VERSION 5.7 ;
  NOWIREEXTENSIONATPIN ON ;
  DIVIDERCHAR "/" ;
  BUSBITCHARS "[]" ;
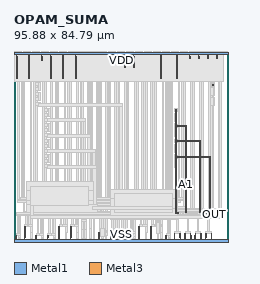
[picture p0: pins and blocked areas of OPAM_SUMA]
MACRO OPAM_SUMA
  CLASS BLOCK ;
  FOREIGN OPAM_SUMA ;
  ORIGIN 1.260 0.000 ;
  SIZE 95.880 BY 84.790 ;
  PIN VSS
    DIRECTION INOUT ;
    USE GROUND ;
    PORT
      LAYER Metal1 ;
        RECT 3.300 4.380 3.660 6.880 ;
        RECT 18.780 4.380 19.140 6.880 ;
        RECT 23.940 4.380 24.300 6.880 ;
        RECT 54.500 4.380 54.860 6.880 ;
        RECT 59.720 4.380 60.080 6.880 ;
        RECT -0.360 2.380 0.000 2.880 ;
        RECT -0.390 1.880 0.000 2.380 ;
        RECT 3.270 1.880 3.660 4.380 ;
        RECT 8.460 2.380 8.820 2.880 ;
        RECT 13.620 2.380 13.980 2.880 ;
        RECT 8.430 1.880 8.820 2.380 ;
        RECT 13.590 1.880 13.980 2.380 ;
        RECT 18.750 1.880 19.140 4.380 ;
        RECT 23.910 1.880 24.300 4.380 ;
        RECT 36.480 3.130 36.840 4.380 ;
        RECT 41.860 3.130 42.220 4.380 ;
        RECT 36.450 1.880 36.840 3.130 ;
        RECT 41.830 1.880 42.220 3.130 ;
        RECT 54.470 1.880 54.860 4.380 ;
        RECT 59.690 1.880 60.080 4.380 ;
        RECT 70.200 2.880 70.560 3.880 ;
        RECT 66.540 2.380 66.900 2.880 ;
        RECT 66.510 1.880 66.900 2.380 ;
        RECT 70.170 1.880 70.560 2.880 ;
        RECT 72.700 2.880 73.060 3.880 ;
        RECT 74.860 2.880 75.220 3.880 ;
        RECT 72.700 1.880 73.090 2.880 ;
        RECT -0.390 0.900 -0.160 1.880 ;
        RECT 3.270 0.900 3.500 1.880 ;
        RECT 8.430 0.900 8.660 1.880 ;
        RECT 13.590 0.900 13.820 1.880 ;
        RECT 18.750 0.900 18.980 1.880 ;
        RECT 23.910 0.900 24.140 1.880 ;
        RECT 36.450 0.900 36.680 1.880 ;
        RECT 41.830 0.900 42.060 1.880 ;
        RECT 54.470 0.900 54.700 1.880 ;
        RECT 59.690 0.900 59.920 1.880 ;
        RECT 66.510 0.900 66.740 1.880 ;
        RECT 70.170 0.900 70.400 1.880 ;
        RECT 72.860 0.900 73.090 1.880 ;
        RECT 74.830 1.880 75.220 2.880 ;
        RECT 77.360 2.880 77.720 3.880 ;
        RECT 79.520 2.880 79.880 3.880 ;
        RECT 77.360 1.880 77.750 2.880 ;
        RECT 74.830 0.900 75.060 1.880 ;
        RECT 77.520 0.900 77.750 1.880 ;
        RECT 79.490 1.880 79.880 2.880 ;
        RECT 82.020 2.880 82.380 3.880 ;
        RECT 84.180 2.880 84.540 3.880 ;
        RECT 82.020 1.880 82.410 2.880 ;
        RECT 79.490 0.900 79.720 1.880 ;
        RECT 82.180 0.900 82.410 1.880 ;
        RECT 84.150 1.880 84.540 2.880 ;
        RECT 86.680 2.880 87.040 3.880 ;
        RECT 86.680 1.880 87.070 2.880 ;
        RECT 84.150 0.900 84.380 1.880 ;
        RECT 86.840 0.900 87.070 1.880 ;
        RECT -1.000 0.000 94.620 0.900 ;
      LAYER Metal3 ;
        RECT -1.260 0.000 94.620 0.900 ;
    END
  END VSS
  PIN VDD
    DIRECTION INOUT ;
    USE POWER ;
    PORT
      LAYER Metal1 ;
        RECT -1.000 83.890 94.620 84.790 ;
        RECT -0.190 82.910 0.040 83.890 ;
        RECT 4.050 83.790 4.530 83.890 ;
        RECT 5.370 82.910 5.600 83.890 ;
        RECT 10.930 82.910 11.160 83.890 ;
        RECT 13.670 83.790 14.150 83.890 ;
        RECT 14.990 82.910 15.220 83.890 ;
        RECT 20.550 82.910 20.780 83.890 ;
        RECT 24.790 83.790 25.270 83.890 ;
        RECT 26.110 82.910 26.340 83.890 ;
        RECT 34.410 83.790 34.890 83.890 ;
        RECT 42.530 83.790 43.010 83.890 ;
        RECT 47.910 82.910 48.140 83.890 ;
        RECT 50.650 83.790 51.130 83.890 ;
        RECT 51.970 82.910 52.200 83.890 ;
        RECT 58.770 83.790 59.250 83.890 ;
        RECT 64.210 82.910 64.440 83.890 ;
        RECT 70.110 83.790 70.590 83.890 ;
        RECT 71.430 82.910 71.660 83.890 ;
        RECT 76.990 82.910 77.220 83.890 ;
        RECT 79.730 83.790 80.210 83.890 ;
        RECT 81.050 82.910 81.280 83.890 ;
        RECT 85.110 82.910 85.340 83.890 ;
        RECT 87.850 83.790 88.330 83.890 ;
        RECT 89.170 82.910 89.400 83.890 ;
        RECT -0.190 77.910 0.200 82.910 ;
        RECT 5.370 77.910 5.760 82.910 ;
        RECT 10.930 81.910 11.320 82.910 ;
        RECT 10.960 80.910 11.320 81.910 ;
        RECT 14.990 77.910 15.380 82.910 ;
        RECT 20.550 77.910 20.940 82.910 ;
        RECT 26.110 77.910 26.500 82.910 ;
        RECT 47.910 80.410 48.300 82.910 ;
        RECT 51.970 80.410 52.360 82.910 ;
        RECT 47.940 77.910 48.300 80.410 ;
        RECT 52.000 77.910 52.360 80.410 ;
        RECT 64.210 77.910 64.600 82.910 ;
        RECT 71.430 77.910 71.820 82.910 ;
        RECT 76.990 82.410 77.380 82.910 ;
        RECT 81.050 82.410 81.440 82.910 ;
        RECT 85.110 82.410 85.500 82.910 ;
        RECT 89.170 82.410 89.560 82.910 ;
        RECT 77.020 81.910 77.380 82.410 ;
        RECT 81.080 81.910 81.440 82.410 ;
        RECT 85.140 81.910 85.500 82.410 ;
        RECT 89.200 81.910 89.560 82.410 ;
        RECT -0.160 72.910 0.200 77.910 ;
        RECT 5.400 72.910 5.760 77.910 ;
        RECT 15.020 72.910 15.380 77.910 ;
        RECT 20.580 72.910 20.940 77.910 ;
        RECT 26.140 72.910 26.500 77.910 ;
        RECT 64.240 72.910 64.600 77.910 ;
        RECT 71.460 72.910 71.820 77.910 ;
      LAYER Metal3 ;
        RECT -1.260 83.890 94.620 84.790 ;
    END
  END VDD
  PIN OUT
    DIRECTION OUTPUT ;
    ANTENNAGATEAREA 4.000000 ;
    ANTENNADIFFAREA 9.240000 ;
    PORT
      LAYER Metal3 ;
      RECT 87.490 69.980 87.890 70.380 ;
      RECT 90.015 12.220 90.415 12.620 ;
    END
  END OUT
  PIN A1
    DIRECTION INPUT ;
    ANTENNAGATEAREA 33.049999 ;
    ANTENNADIFFAREA 1.892000 ;
    PORT
      LAYER Metal3 ;
      RECT 70.700 58.580 71.100 58.980 ;
      RECT 70.780 52.080 71.080 58.580 ;
        RECT 70.700 52.030 71.100 52.080 ;
      RECT 70.700 51.730 75.700 52.030 ;
        RECT 70.700 51.680 71.100 51.730 ;
      RECT 70.780 45.180 71.080 51.680 ;
        RECT 70.700 45.130 71.100 45.180 ;
      RECT 75.400 45.130 75.700 51.730 ;
      RECT 70.700 44.830 81.800 45.130 ;
        RECT 70.700 44.780 71.100 44.830 ;
      RECT 70.780 38.280 71.080 44.780 ;
        RECT 70.700 38.230 71.100 38.280 ;
      RECT 75.400 38.230 75.700 44.830 ;
      RECT 81.500 38.230 81.800 44.830 ;
      RECT 70.700 37.930 86.460 38.230 ;
        RECT 70.700 37.880 71.100 37.930 ;
      RECT 70.780 13.280 71.080 37.880 ;
      RECT 70.730 12.880 71.130 13.280 ;
      RECT 71.730 12.880 72.130 13.360 ;
      RECT 75.400 13.280 75.700 37.930 ;
      RECT 81.500 13.280 81.800 37.930 ;
      RECT 83.150 12.880 84.450 13.360 ;
      RECT 86.160 13.280 86.460 37.930 ;
      RECT 86.110 12.880 86.510 13.280 ;
    END
  END A1
  OBS
      LAYER Via1 ;
        RECT 70.470 40.050 71.330 43.660 ;
        RECT 13.990 42.300 14.850 45.910 ;
        RECT 0.910 1.650 1.730 2.150 ;
        RECT 11.230 1.650 12.050 2.150 ;
        RECT 16.390 1.650 17.210 2.150 ;
        RECT 67.810 1.650 68.630 2.150 ;
        RECT 37.830 1.650 38.650 2.450 ;
        RECT 43.210 1.650 44.030 2.450 ;
        RECT 46.950 1.650 47.770 2.650 ;
        RECT 48.450 1.650 49.270 2.650 ;
        RECT 50.610 1.650 51.430 2.650 ;
        RECT 52.110 1.650 52.930 2.650 ;
        RECT 0.910 2.150 1.760 2.870 ;
        RECT 11.230 2.150 12.080 2.870 ;
        RECT 16.390 2.150 17.240 2.870 ;
        RECT 67.810 2.150 68.660 2.870 ;
        RECT 0.000 2.870 1.760 2.880 ;
        RECT 8.820 2.870 10.120 2.880 ;
        RECT 13.980 2.870 15.280 2.880 ;
        RECT 66.900 2.870 68.660 2.880 ;
        RECT 39.410 1.650 40.230 2.900 ;
        RECT 44.790 1.650 45.610 2.900 ;
        RECT -0.160 2.880 1.760 3.690 ;
        RECT 8.660 2.880 10.120 3.690 ;
        RECT 10.160 2.870 12.080 3.690 ;
        RECT 13.820 2.880 15.280 3.690 ;
        RECT 15.320 2.870 17.240 3.690 ;
        RECT 66.740 2.880 68.660 3.690 ;
        RECT 62.570 1.650 63.390 3.700 ;
        RECT 46.920 2.650 47.770 3.870 ;
        RECT 48.450 2.650 49.400 3.870 ;
        RECT 50.580 2.650 51.430 3.870 ;
        RECT 52.110 2.650 52.960 3.870 ;
        RECT 70.560 3.870 72.700 3.880 ;
        RECT 75.220 3.870 77.360 3.880 ;
        RECT 79.880 3.870 82.020 3.880 ;
        RECT 84.540 3.870 86.680 3.880 ;
        RECT 6.070 1.650 6.890 4.150 ;
        RECT 21.550 1.650 22.370 4.150 ;
        RECT 26.710 1.650 27.530 4.150 ;
        RECT 57.270 1.650 58.090 4.150 ;
        RECT 64.150 1.650 64.970 4.150 ;
        RECT 37.560 2.450 38.920 4.370 ;
        RECT 39.410 2.900 40.260 4.370 ;
        RECT 42.940 2.450 44.300 4.370 ;
        RECT 44.790 2.900 45.640 4.370 ;
        RECT 36.840 4.370 40.260 4.380 ;
        RECT 42.220 4.370 45.640 4.380 ;
        RECT 70.400 3.880 72.860 4.690 ;
        RECT 75.060 3.880 77.520 4.690 ;
        RECT 79.720 3.880 82.180 4.690 ;
        RECT 84.380 3.880 86.840 4.690 ;
        RECT 46.920 3.870 49.400 4.690 ;
        RECT 50.580 3.870 52.960 4.690 ;
        RECT 36.680 4.380 40.260 5.190 ;
        RECT 42.060 4.380 45.640 5.190 ;
        RECT 28.870 1.650 29.690 5.400 ;
        RECT 30.370 1.650 31.190 5.400 ;
        RECT 32.530 1.650 33.350 5.900 ;
        RECT 34.030 1.650 34.850 5.900 ;
        RECT 37.065 5.190 39.415 6.040 ;
        RECT 42.445 5.190 44.795 6.040 ;
        RECT 6.070 4.150 6.920 6.870 ;
        RECT 21.550 4.150 22.400 6.870 ;
        RECT 26.710 4.150 27.560 6.870 ;
        RECT 57.270 4.150 58.120 6.870 ;
        RECT 62.300 3.700 63.660 6.870 ;
        RECT 64.150 4.150 65.000 6.870 ;
        RECT 3.660 6.870 4.960 6.880 ;
        RECT 19.140 6.870 20.440 6.880 ;
        RECT 24.300 6.870 25.600 6.880 ;
        RECT 54.860 6.870 56.160 6.880 ;
        RECT 60.080 6.870 61.380 6.880 ;
        RECT 3.500 6.880 4.960 7.690 ;
        RECT 5.000 6.870 6.920 7.690 ;
        RECT 18.980 6.880 20.440 7.690 ;
        RECT 20.480 6.870 22.400 7.690 ;
        RECT 24.140 6.880 25.600 7.690 ;
        RECT 25.640 6.870 27.560 7.690 ;
        RECT 54.700 6.880 56.160 7.690 ;
        RECT 56.200 6.870 58.120 7.690 ;
        RECT 59.920 6.880 61.380 7.690 ;
        RECT 61.420 6.870 65.000 7.690 ;
        RECT 61.805 7.690 64.155 8.540 ;
        RECT 28.840 5.400 29.690 9.370 ;
        RECT 30.370 5.400 31.220 9.370 ;
        RECT 28.840 9.370 31.220 10.190 ;
        RECT 32.500 5.900 33.350 10.370 ;
        RECT 34.030 5.900 34.880 10.370 ;
        RECT 32.500 10.370 34.880 11.190 ;
        RECT 67.970 3.690 68.660 11.730 ;
        RECT 80.605 4.690 81.295 11.730 ;
        RECT 0.225 3.690 0.915 11.740 ;
        RECT 1.070 3.690 1.760 11.740 ;
        RECT 5.385 7.690 6.075 11.740 ;
        RECT 6.230 7.690 6.920 11.740 ;
        RECT 20.865 7.690 21.555 11.740 ;
        RECT 21.710 7.690 22.400 11.740 ;
        RECT 26.025 7.690 26.715 11.740 ;
        RECT 26.870 7.690 27.560 11.740 ;
        RECT 37.895 6.040 38.585 11.740 ;
        RECT 38.725 6.040 39.415 11.740 ;
        RECT 39.570 5.190 40.260 11.740 ;
        RECT 43.275 6.040 43.965 11.740 ;
        RECT 44.105 6.040 44.795 11.740 ;
        RECT 44.950 5.190 45.640 11.740 ;
        RECT 56.585 7.690 57.275 11.740 ;
        RECT 57.430 7.690 58.120 11.740 ;
        RECT 61.805 8.540 62.495 11.740 ;
        RECT 62.635 8.540 63.325 11.740 ;
        RECT 67.125 3.690 67.815 11.740 ;
        RECT 67.970 11.730 69.705 11.740 ;
        RECT 87.025 11.730 88.405 11.740 ;
        RECT 89.525 11.730 90.905 11.740 ;
        RECT -0.110 11.740 2.095 11.790 ;
        RECT 2.435 11.740 3.795 11.790 ;
        RECT 3.885 7.690 4.575 11.790 ;
        RECT 5.050 11.740 6.920 11.790 ;
        RECT 9.045 3.690 9.735 11.790 ;
        RECT 10.545 3.690 11.235 11.790 ;
        RECT 11.390 3.690 12.080 11.790 ;
        RECT 14.205 3.690 14.895 11.790 ;
        RECT 15.735 3.690 16.425 11.790 ;
        RECT 16.550 3.690 17.240 11.790 ;
        RECT 19.365 7.690 20.055 11.790 ;
        RECT 20.530 11.740 22.400 11.790 ;
        RECT 24.525 7.690 25.215 11.790 ;
        RECT 25.690 11.740 27.560 11.790 ;
        RECT 28.840 10.190 29.530 11.790 ;
        RECT 29.685 10.190 30.375 11.790 ;
        RECT 30.530 10.190 31.220 11.790 ;
        RECT 32.500 11.190 33.190 11.790 ;
        RECT 33.345 11.190 34.035 11.790 ;
        RECT 34.190 11.190 34.880 11.790 ;
        RECT 37.065 6.040 37.755 11.790 ;
        RECT 37.895 11.740 40.260 11.790 ;
        RECT 42.445 6.040 43.135 11.790 ;
        RECT 43.275 11.740 45.640 11.790 ;
        RECT 46.920 4.690 47.610 11.790 ;
        RECT 47.765 4.690 48.455 11.790 ;
        RECT 48.710 4.690 49.400 11.790 ;
        RECT 50.580 4.690 51.270 11.790 ;
        RECT 51.425 4.690 52.115 11.790 ;
        RECT 52.270 4.690 52.960 11.790 ;
        RECT 55.085 7.690 55.775 11.790 ;
        RECT 56.250 11.740 58.120 11.790 ;
        RECT 60.305 7.690 60.995 11.790 ;
        RECT 61.470 11.740 63.325 11.790 ;
        RECT 67.125 11.740 69.705 11.790 ;
        RECT 71.285 4.690 71.975 11.790 ;
        RECT 73.525 11.730 74.905 11.790 ;
        RECT 75.945 4.690 76.635 11.790 ;
        RECT 78.115 11.740 79.475 11.790 ;
        RECT 79.625 11.730 81.295 11.790 ;
        RECT 82.175 11.740 83.535 11.790 ;
        RECT 85.265 4.690 85.955 11.790 ;
        RECT 86.235 11.740 88.405 11.790 ;
        RECT 89.525 11.740 91.655 11.790 ;
        RECT -0.110 11.790 63.325 12.400 ;
        RECT 63.465 8.540 64.155 12.400 ;
        RECT 67.125 11.790 91.655 12.450 ;
        RECT -0.110 12.400 64.155 13.050 ;
        RECT 67.125 12.450 92.100 13.060 ;
        RECT -0.110 13.050 2.095 13.100 ;
        RECT 2.435 13.050 56.110 13.100 ;
        RECT 56.250 13.050 58.120 13.100 ;
        RECT 3.550 13.100 56.110 13.110 ;
        RECT 57.430 13.100 58.120 13.110 ;
        RECT 59.825 13.050 64.155 13.110 ;
        RECT 64.310 7.690 65.000 13.110 ;
        RECT 66.790 13.060 92.100 13.110 ;
        RECT 3.550 13.110 92.100 13.710 ;
        RECT 74.860 13.710 78.240 13.720 ;
        RECT 78.450 13.710 80.040 13.720 ;
        RECT 80.270 13.710 82.340 13.720 ;
        RECT 82.510 13.710 87.260 13.720 ;
        RECT 90.630 13.710 91.320 13.720 ;
        RECT 3.550 13.710 4.910 13.760 ;
        RECT 5.895 13.710 7.255 13.760 ;
        RECT 7.995 13.710 9.735 13.760 ;
        RECT 19.030 13.710 20.390 13.760 ;
        RECT 80.270 13.720 87.260 13.760 ;
        RECT 44.615 13.710 68.150 13.770 ;
        RECT 69.340 13.710 73.720 13.770 ;
        RECT 74.860 13.720 80.040 13.770 ;
        RECT 80.960 13.760 84.940 13.770 ;
        RECT 85.390 13.760 87.260 13.770 ;
        RECT 87.920 13.710 89.300 13.770 ;
        RECT 89.450 13.720 91.320 13.770 ;
        RECT 21.375 13.710 37.755 14.370 ;
        RECT 42.445 13.710 43.135 14.380 ;
        RECT 43.275 13.710 43.965 14.380 ;
        RECT 21.375 14.370 22.735 14.420 ;
        RECT 44.615 13.770 91.320 14.420 ;
        RECT 23.175 14.370 37.755 14.420 ;
        RECT 23.175 14.420 37.035 14.430 ;
        RECT 37.065 14.420 37.755 14.430 ;
        RECT 37.895 13.710 38.585 14.430 ;
        RECT 39.570 13.710 40.260 14.430 ;
        RECT 42.445 14.380 44.300 14.430 ;
        RECT 23.175 14.430 44.300 15.030 ;
        RECT 44.975 14.420 91.320 15.030 ;
        RECT 28.735 15.030 44.300 15.040 ;
        RECT 23.175 15.030 24.535 15.080 ;
        RECT 28.735 15.040 44.645 15.080 ;
        RECT 44.975 15.030 75.415 15.080 ;
        RECT 77.270 15.030 79.140 15.080 ;
        RECT 81.330 15.030 83.200 15.080 ;
        RECT 85.390 15.030 87.260 15.080 ;
        RECT 89.450 15.030 91.320 15.080 ;
        RECT 29.070 15.080 44.645 15.090 ;
        RECT 45.310 15.080 75.415 15.090 ;
        RECT 29.070 15.090 75.415 15.690 ;
        RECT 74.055 15.690 75.415 15.740 ;
        RECT 29.070 15.690 54.455 15.750 ;
        RECT 56.310 15.690 69.855 15.750 ;
        RECT 30.195 15.750 69.855 16.350 ;
        RECT 34.190 16.350 34.880 16.360 ;
        RECT 30.195 16.350 32.265 16.400 ;
        RECT 64.345 16.350 69.855 16.400 ;
        RECT 59.860 16.350 62.240 16.400 ;
        RECT 30.885 16.400 32.265 16.410 ;
        RECT 33.855 16.360 35.215 16.410 ;
        RECT 35.500 16.350 36.190 16.410 ;
        RECT 36.345 16.350 58.515 16.410 ;
        RECT 64.345 16.400 68.675 17.010 ;
        RECT 33.855 16.410 58.515 17.010 ;
        RECT 53.430 17.010 54.120 17.020 ;
        RECT 56.645 17.010 58.515 17.020 ;
        RECT 55.465 17.020 58.515 17.060 ;
        RECT 64.490 17.010 65.850 17.060 ;
        RECT 66.820 17.010 68.675 17.060 ;
        RECT 33.855 17.010 50.395 17.070 ;
        RECT 52.250 17.020 54.120 17.070 ;
        RECT 55.465 17.060 57.335 17.070 ;
        RECT 33.855 17.070 57.335 17.670 ;
        RECT 10.545 13.710 11.235 17.680 ;
        RECT 11.390 13.710 12.080 17.680 ;
        RECT 14.205 13.710 14.895 17.680 ;
        RECT 15.735 13.710 16.425 17.680 ;
        RECT 33.855 17.670 35.215 17.720 ;
        RECT 35.500 17.670 40.585 17.720 ;
        RECT 0.090 17.680 1.450 17.730 ;
        RECT 2.770 13.100 3.460 17.730 ;
        RECT 5.650 17.680 7.010 17.730 ;
        RECT 8.330 13.760 9.020 17.730 ;
        RECT 9.045 13.760 9.735 17.730 ;
        RECT 10.545 17.680 12.415 17.730 ;
        RECT 14.205 17.680 16.425 17.730 ;
        RECT 16.550 13.710 17.240 17.730 ;
        RECT 17.615 17.680 18.975 17.730 ;
        RECT 20.830 17.680 22.190 17.730 ;
        RECT 23.510 15.080 24.200 17.730 ;
        RECT 26.390 17.680 27.750 17.730 ;
        RECT 29.070 15.750 29.760 17.730 ;
        RECT 31.440 16.410 32.130 17.730 ;
        RECT 32.285 16.350 32.975 17.730 ;
        RECT 33.130 16.350 33.820 17.730 ;
        RECT 35.500 17.720 40.250 17.730 ;
        RECT 40.915 17.670 57.335 17.730 ;
        RECT 57.490 17.060 58.180 17.730 ;
        RECT 59.860 16.400 60.550 17.730 ;
        RECT 60.705 16.400 61.395 17.730 ;
        RECT 61.550 16.400 62.240 17.730 ;
        RECT 64.825 17.060 65.515 17.730 ;
        RECT 67.155 17.060 67.845 17.730 ;
        RECT 67.985 17.060 68.675 17.730 ;
        RECT 68.830 16.400 69.520 17.730 ;
        RECT 71.710 17.680 73.070 17.730 ;
        RECT 74.390 15.740 75.080 18.340 ;
        RECT 0.090 17.730 73.070 18.390 ;
        RECT 73.210 18.340 75.080 18.390 ;
        RECT 0.090 18.390 75.080 18.990 ;
        RECT 0.090 18.990 1.450 19.040 ;
        RECT 1.590 18.990 75.080 19.650 ;
        RECT 1.590 19.650 3.460 19.700 ;
        RECT 7.150 19.650 10.070 19.700 ;
        RECT 10.210 19.650 13.415 19.700 ;
        RECT 13.870 19.650 18.640 19.700 ;
        RECT 22.330 19.650 24.200 19.700 ;
        RECT 27.890 19.650 29.760 19.700 ;
        RECT 65.990 19.650 67.845 19.700 ;
        RECT 73.210 19.650 75.080 19.700 ;
        RECT 39.560 19.650 41.940 19.700 ;
        RECT 43.620 19.650 46.000 19.700 ;
        RECT 12.390 19.700 13.080 33.150 ;
        RECT 13.730 32.890 15.110 33.150 ;
        RECT 12.390 33.150 15.110 34.270 ;
        RECT 12.390 34.270 13.760 34.510 ;
        RECT 13.990 34.270 14.850 34.510 ;
        RECT 12.390 34.510 13.080 35.400 ;
        RECT 12.390 35.400 13.760 36.760 ;
        RECT 12.390 36.760 13.080 37.650 ;
        RECT 12.390 37.650 13.760 39.010 ;
        RECT 12.390 39.010 13.080 40.050 ;
        RECT 13.730 39.790 15.110 40.050 ;
        RECT 12.390 40.050 15.110 41.170 ;
        RECT 12.390 41.170 13.760 41.410 ;
        RECT 13.990 41.170 14.850 41.410 ;
        RECT 12.390 41.410 13.080 42.300 ;
        RECT 12.390 42.300 13.760 43.660 ;
        RECT 12.390 43.660 13.080 44.550 ;
        RECT 12.390 44.550 13.760 45.910 ;
        RECT 12.390 45.910 13.080 46.950 ;
        RECT 13.730 46.690 15.110 46.950 ;
        RECT 12.390 46.950 15.110 48.070 ;
        RECT 12.390 48.070 13.760 48.310 ;
        RECT 13.990 48.070 14.850 48.310 ;
        RECT 12.390 48.310 13.080 49.200 ;
        RECT 12.390 49.200 13.760 50.560 ;
        RECT 12.390 50.560 13.080 51.450 ;
        RECT 12.390 51.450 13.760 52.810 ;
        RECT 12.390 52.810 13.080 53.850 ;
        RECT 13.730 53.590 15.110 53.850 ;
        RECT 12.390 53.850 15.110 54.970 ;
        RECT 12.390 54.970 13.760 55.210 ;
        RECT 13.990 54.970 14.850 55.210 ;
        RECT 12.390 55.210 13.080 56.100 ;
        RECT 12.390 56.100 13.760 57.460 ;
        RECT 12.390 57.460 13.080 58.350 ;
        RECT 12.390 58.350 13.760 59.710 ;
        RECT 8.330 19.700 9.020 60.750 ;
        RECT 9.630 60.490 11.010 60.750 ;
        RECT 86.570 15.080 87.260 60.750 ;
        RECT 8.330 60.750 11.010 61.870 ;
        RECT 8.330 61.870 9.660 62.110 ;
        RECT 9.890 61.870 10.750 62.110 ;
        RECT 8.330 62.110 9.020 63.000 ;
        RECT 8.330 63.000 9.660 64.360 ;
        RECT 86.570 60.750 88.120 64.360 ;
        RECT 8.330 64.360 9.020 65.250 ;
        RECT 86.570 64.360 87.260 65.250 ;
        RECT 8.330 65.250 9.660 66.610 ;
        RECT 8.330 66.610 9.020 67.500 ;
        RECT 8.330 67.500 9.660 68.860 ;
        RECT 86.570 65.250 88.120 68.860 ;
        RECT 86.570 68.860 87.260 69.490 ;
        RECT 8.330 68.860 9.020 69.750 ;
        RECT 86.570 69.490 88.380 70.870 ;
        RECT 8.330 69.750 9.660 71.110 ;
        RECT 86.570 70.870 88.120 71.110 ;
        RECT 66.325 19.700 67.015 71.250 ;
        RECT 67.155 19.700 67.845 71.250 ;
        RECT 67.985 19.650 68.675 71.250 ;
        RECT 0.425 19.040 1.115 72.100 ;
        RECT 1.925 19.700 2.615 72.100 ;
        RECT 2.770 19.700 3.460 72.100 ;
        RECT 5.985 19.650 6.675 72.100 ;
        RECT 7.485 19.700 8.175 72.100 ;
        RECT 8.330 71.110 9.020 72.100 ;
        RECT 15.220 19.700 15.910 72.100 ;
        RECT 17.210 19.700 17.900 72.100 ;
        RECT 17.950 19.700 18.640 72.100 ;
        RECT 21.165 19.650 21.855 72.100 ;
        RECT 22.665 19.700 23.355 72.100 ;
        RECT 23.510 19.700 24.200 72.100 ;
        RECT 26.725 19.650 27.415 72.100 ;
        RECT 28.225 19.700 28.915 72.100 ;
        RECT 29.070 19.700 29.760 72.100 ;
        RECT 39.560 19.700 40.250 72.100 ;
        RECT 40.405 19.700 41.095 72.100 ;
        RECT 41.250 19.700 41.940 72.100 ;
        RECT 43.620 19.700 44.310 72.100 ;
        RECT 44.465 19.700 45.155 72.100 ;
        RECT 45.310 19.700 46.000 72.100 ;
        RECT 64.825 19.650 65.515 72.100 ;
        RECT 66.325 71.250 68.675 72.100 ;
        RECT 68.830 19.650 69.520 72.100 ;
        RECT 72.045 19.650 72.735 72.100 ;
        RECT 73.545 19.700 74.235 72.100 ;
        RECT 74.390 19.700 75.080 72.100 ;
        RECT 0.040 72.100 1.500 72.910 ;
        RECT 5.600 72.100 7.060 72.910 ;
        RECT 15.220 72.100 16.680 72.910 ;
        RECT 20.780 72.100 22.240 72.910 ;
        RECT 26.340 72.100 27.800 72.910 ;
        RECT 64.440 72.100 65.900 72.910 ;
        RECT 71.660 72.100 73.120 72.910 ;
        RECT 0.200 72.910 1.500 72.920 ;
        RECT 1.540 72.100 3.460 72.920 ;
        RECT 5.760 72.910 7.060 72.920 ;
        RECT 7.100 72.100 9.020 72.920 ;
        RECT 15.380 72.910 16.680 72.920 ;
        RECT 16.720 72.100 18.640 72.920 ;
        RECT 20.940 72.910 22.240 72.920 ;
        RECT 22.280 72.100 24.200 72.920 ;
        RECT 26.500 72.910 27.800 72.920 ;
        RECT 27.840 72.100 29.760 72.920 ;
        RECT 64.600 72.910 65.900 72.920 ;
        RECT 65.940 72.100 69.520 72.920 ;
        RECT 71.820 72.910 73.120 72.920 ;
        RECT 73.160 72.100 75.080 72.920 ;
        RECT 39.560 72.100 41.940 72.920 ;
        RECT 43.620 72.100 46.000 72.920 ;
        RECT 48.140 19.650 48.830 77.100 ;
        RECT 49.370 19.650 50.060 77.100 ;
        RECT 52.585 19.650 53.275 77.100 ;
        RECT 53.430 19.650 54.120 77.100 ;
        RECT 48.140 77.100 50.060 77.910 ;
        RECT 52.200 77.100 54.120 77.910 ;
        RECT 48.300 77.910 50.060 77.920 ;
        RECT 52.360 77.910 54.120 77.920 ;
        RECT 55.800 19.650 56.490 78.100 ;
        RECT 56.645 19.650 57.335 78.100 ;
        RECT 57.490 19.650 58.180 78.100 ;
        RECT 59.860 19.650 60.550 78.100 ;
        RECT 60.705 19.650 61.395 78.100 ;
        RECT 61.550 19.650 62.240 78.100 ;
        RECT 2.610 72.920 3.460 78.140 ;
        RECT 8.170 72.920 9.020 78.140 ;
        RECT 17.790 72.920 18.640 78.140 ;
        RECT 23.350 72.920 24.200 78.140 ;
        RECT 28.910 72.920 29.760 78.140 ;
        RECT 39.560 72.920 40.410 78.140 ;
        RECT 41.090 72.920 41.940 78.140 ;
        RECT 43.620 72.920 44.470 78.140 ;
        RECT 45.150 72.920 46.000 78.140 ;
        RECT 68.670 72.920 69.520 78.140 ;
        RECT 74.230 72.920 75.080 78.140 ;
        RECT 66.820 72.920 68.180 78.590 ;
        RECT 55.800 78.100 58.180 78.920 ;
        RECT 59.860 78.100 62.240 78.920 ;
        RECT 11.545 19.700 12.235 80.100 ;
        RECT 12.390 59.710 13.080 80.100 ;
        RECT 49.210 77.920 50.060 80.640 ;
        RECT 53.270 77.920 54.120 80.640 ;
        RECT 11.160 80.100 13.080 80.910 ;
        RECT 11.320 80.910 13.080 80.920 ;
        RECT 77.605 15.080 78.295 81.100 ;
        RECT 78.450 15.080 79.140 81.100 ;
        RECT 81.665 15.080 82.355 81.100 ;
        RECT 82.510 15.080 83.200 81.100 ;
        RECT 85.725 15.080 86.415 81.100 ;
        RECT 86.570 71.110 87.260 81.100 ;
        RECT 89.785 15.080 90.475 81.100 ;
        RECT 90.630 15.080 91.320 81.100 ;
        RECT 55.800 78.920 56.650 81.140 ;
        RECT 57.330 78.920 58.180 81.140 ;
        RECT 59.860 78.920 60.710 81.140 ;
        RECT 61.390 78.920 62.240 81.140 ;
        RECT 31.440 19.650 32.130 81.550 ;
        RECT 32.285 19.650 32.975 81.550 ;
        RECT 33.130 19.650 33.820 81.550 ;
        RECT 35.500 19.650 36.190 81.600 ;
        RECT 36.345 19.650 37.035 81.600 ;
        RECT 37.190 19.650 37.880 81.600 ;
        RECT 77.220 81.100 79.140 81.910 ;
        RECT 81.280 81.100 83.200 81.910 ;
        RECT 85.340 81.100 87.260 81.910 ;
        RECT 89.400 81.100 91.320 81.910 ;
        RECT 77.380 81.910 79.140 81.920 ;
        RECT 81.440 81.910 83.200 81.920 ;
        RECT 85.500 81.910 87.260 81.920 ;
        RECT 89.560 81.910 91.320 81.920 ;
        RECT 12.230 80.920 13.080 82.140 ;
        RECT 31.440 81.550 33.820 82.370 ;
        RECT 35.500 81.600 37.880 82.420 ;
        RECT 78.290 81.920 79.140 82.640 ;
        RECT 82.350 81.920 83.200 82.640 ;
        RECT 86.410 81.920 87.260 82.640 ;
        RECT 90.470 81.920 91.320 82.640 ;
        RECT 31.440 82.370 32.290 82.865 ;
        RECT 32.970 82.370 33.820 82.865 ;
        RECT 35.500 82.420 36.350 82.890 ;
        RECT 37.030 82.420 37.880 82.890 ;
        RECT 2.610 78.140 3.430 83.140 ;
        RECT 8.170 78.140 8.990 83.140 ;
        RECT 12.230 82.140 13.050 83.140 ;
        RECT 17.790 78.140 18.610 83.140 ;
        RECT 23.350 78.140 24.170 83.140 ;
        RECT 28.910 78.140 29.730 83.140 ;
        RECT 31.470 82.865 32.290 83.140 ;
        RECT 32.970 82.865 33.790 83.140 ;
        RECT 35.530 82.890 36.350 83.140 ;
        RECT 37.030 82.890 37.850 83.140 ;
        RECT 39.590 78.140 40.410 83.140 ;
        RECT 41.090 78.140 41.910 83.140 ;
        RECT 43.650 78.140 44.470 83.140 ;
        RECT 45.150 78.140 45.970 83.140 ;
        RECT 49.210 80.640 50.030 83.140 ;
        RECT 53.270 80.640 54.090 83.140 ;
        RECT 55.830 81.140 56.650 83.140 ;
        RECT 57.330 81.140 58.150 83.140 ;
        RECT 59.890 81.140 60.710 83.140 ;
        RECT 61.390 81.140 62.210 83.140 ;
        RECT 67.090 78.590 67.910 83.140 ;
        RECT 68.670 78.140 69.490 83.140 ;
        RECT 74.230 78.140 75.050 83.140 ;
        RECT 78.290 82.640 79.110 83.140 ;
        RECT 82.350 82.640 83.170 83.140 ;
        RECT 86.410 82.640 87.230 83.140 ;
        RECT 90.470 82.640 91.290 83.140 ;
        RECT 70.470 46.950 71.330 50.560 ;
        RECT 70.210 51.190 71.590 52.570 ;
        RECT 70.470 52.570 71.330 52.810 ;
        RECT 70.470 53.850 71.330 57.460 ;
        RECT 70.210 58.090 71.590 59.470 ;
        RECT 70.470 59.470 71.330 59.710 ;
        RECT 70.210 44.290 71.590 45.670 ;
        RECT 70.470 45.670 71.330 45.910 ;
        RECT 46.850 83.650 48.230 85.030 ;
        RECT 48.850 83.650 50.230 85.030 ;
        RECT 50.850 83.650 52.230 85.030 ;
        RECT 52.850 83.650 54.230 85.030 ;
        RECT 54.850 83.650 56.230 85.030 ;
        RECT 56.850 83.650 58.230 85.030 ;
        RECT 58.850 83.650 60.230 85.030 ;
        RECT 60.850 83.650 62.230 85.030 ;
        RECT 62.850 83.650 64.230 85.030 ;
        RECT 64.850 83.650 66.230 85.030 ;
        RECT 66.850 83.650 68.230 85.030 ;
        RECT 68.850 83.650 70.230 85.030 ;
        RECT 70.850 83.650 72.230 85.030 ;
        RECT 72.850 83.650 74.230 85.030 ;
        RECT 74.850 83.650 76.230 85.030 ;
        RECT 76.850 83.650 78.230 85.030 ;
        RECT 78.850 83.650 80.230 85.030 ;
        RECT 80.850 83.650 82.230 85.030 ;
        RECT 82.850 83.650 84.230 85.030 ;
        RECT 84.850 83.650 86.230 85.030 ;
        RECT 86.850 83.650 88.230 85.030 ;
        RECT 88.850 83.650 90.230 85.030 ;
        RECT 90.850 83.650 92.230 85.030 ;
        RECT 92.850 83.650 94.230 85.030 ;
        RECT 38.850 83.650 40.230 85.030 ;
        RECT 40.850 83.650 42.230 85.030 ;
        RECT 42.850 83.650 44.230 85.030 ;
        RECT 44.850 83.650 46.230 85.030 ;
        RECT 13.990 49.200 14.850 52.810 ;
        RECT 9.890 63.000 10.750 66.610 ;
        RECT 9.890 67.500 10.750 71.110 ;
        RECT 13.990 56.100 14.850 59.710 ;
        RECT -1.150 83.650 0.230 85.030 ;
        RECT 0.850 83.650 2.230 85.030 ;
        RECT 2.850 83.650 4.230 85.030 ;
        RECT 4.850 83.650 6.230 85.030 ;
        RECT 6.850 83.650 8.230 85.030 ;
        RECT 8.850 83.650 10.230 85.030 ;
        RECT 10.850 83.650 12.230 85.030 ;
        RECT 12.850 83.650 14.230 85.030 ;
        RECT 14.850 83.650 16.230 85.030 ;
        RECT 16.850 83.650 18.230 85.030 ;
        RECT 18.850 83.650 20.230 85.030 ;
        RECT 20.850 83.650 22.230 85.030 ;
        RECT 22.850 83.650 24.230 85.030 ;
        RECT 24.850 83.650 26.230 85.030 ;
        RECT 26.850 83.650 28.230 85.030 ;
        RECT 28.850 83.650 30.230 85.030 ;
        RECT 30.850 83.650 32.230 85.030 ;
        RECT 32.850 83.650 34.230 85.030 ;
        RECT 34.850 83.650 36.230 85.030 ;
        RECT 36.850 83.650 38.230 85.030 ;
        RECT 18.850 -0.240 20.230 1.140 ;
        RECT 20.850 -0.240 22.230 1.140 ;
        RECT 22.850 -0.240 24.230 1.140 ;
        RECT 24.850 -0.240 26.230 1.140 ;
        RECT 26.850 -0.240 28.230 1.140 ;
        RECT 28.850 -0.240 30.230 1.140 ;
        RECT 30.850 -0.240 32.230 1.140 ;
        RECT 32.850 -0.240 34.230 1.140 ;
        RECT 34.850 -0.240 36.230 1.140 ;
        RECT 36.850 -0.240 38.230 1.140 ;
        RECT 38.850 -0.240 40.230 1.140 ;
        RECT 40.850 -0.240 42.230 1.140 ;
        RECT 42.850 -0.240 44.230 1.140 ;
        RECT 44.850 -0.240 46.230 1.140 ;
        RECT 13.990 35.400 14.850 39.010 ;
        RECT -1.150 -0.240 0.230 1.140 ;
        RECT 0.850 -0.240 2.230 1.140 ;
        RECT 2.850 -0.240 4.230 1.140 ;
        RECT 4.850 -0.240 6.230 1.140 ;
        RECT 6.850 -0.240 8.230 1.140 ;
        RECT 8.850 -0.240 10.230 1.140 ;
        RECT 10.850 -0.240 12.230 1.140 ;
        RECT 12.850 -0.240 14.230 1.140 ;
        RECT 14.850 -0.240 16.230 1.140 ;
        RECT 16.850 -0.240 18.230 1.140 ;
        RECT 64.850 -0.240 66.230 1.140 ;
        RECT 66.850 -0.240 68.230 1.140 ;
        RECT 68.850 -0.240 70.230 1.140 ;
        RECT 70.850 -0.240 72.230 1.140 ;
        RECT 72.850 -0.240 74.230 1.140 ;
        RECT 74.850 -0.240 76.230 1.140 ;
        RECT 76.850 -0.240 78.230 1.140 ;
        RECT 78.850 -0.240 80.230 1.140 ;
        RECT 80.850 -0.240 82.230 1.140 ;
        RECT 82.850 -0.240 84.230 1.140 ;
        RECT 84.850 -0.240 86.230 1.140 ;
        RECT 86.850 -0.240 88.230 1.140 ;
        RECT 88.850 -0.240 90.230 1.140 ;
        RECT 90.850 -0.240 92.230 1.140 ;
        RECT 92.850 -0.240 94.230 1.140 ;
        RECT 70.470 33.150 71.330 36.760 ;
        RECT 46.850 -0.240 48.230 1.140 ;
        RECT 70.210 37.390 71.590 38.770 ;
        RECT 70.470 38.770 71.330 39.010 ;
        RECT 48.850 -0.240 50.230 1.140 ;
        RECT 50.850 -0.240 52.230 1.140 ;
        RECT 52.850 -0.240 54.230 1.140 ;
        RECT 54.850 -0.240 56.230 1.140 ;
        RECT 56.850 -0.240 58.230 1.140 ;
        RECT 58.850 -0.240 60.230 1.140 ;
        RECT 60.850 -0.240 62.230 1.140 ;
        RECT 62.850 -0.240 64.230 1.140 ;
      LAYER Via2 ;
        RECT 68.325 11.730 69.705 11.740 ;
        RECT 87.025 11.730 88.405 11.740 ;
        RECT 89.525 11.730 90.905 11.740 ;
        RECT -0.110 11.740 2.095 11.790 ;
        RECT 2.435 11.740 3.795 11.790 ;
        RECT 5.050 11.740 6.410 11.790 ;
        RECT 20.530 11.740 21.890 11.790 ;
        RECT 25.690 11.740 27.050 11.790 ;
        RECT 38.390 11.740 39.750 11.790 ;
        RECT 43.770 11.740 45.130 11.790 ;
        RECT 56.250 11.740 57.610 11.790 ;
        RECT 61.470 11.740 62.830 11.790 ;
        RECT 67.635 11.740 69.705 11.790 ;
        RECT 73.525 11.730 74.905 11.790 ;
        RECT 78.115 11.740 79.475 11.790 ;
        RECT 79.625 11.730 81.005 11.790 ;
        RECT 82.175 11.740 83.535 11.790 ;
        RECT 86.235 11.740 88.405 11.790 ;
        RECT 89.525 11.740 91.655 11.790 ;
        RECT -0.110 11.790 62.830 12.400 ;
        RECT -0.110 12.400 63.660 12.450 ;
        RECT 67.635 11.790 91.655 12.450 ;
        RECT -0.110 12.450 63.805 13.050 ;
        RECT 67.635 12.450 92.100 13.060 ;
        RECT -0.110 13.050 2.095 13.100 ;
        RECT 2.435 13.050 56.110 13.100 ;
        RECT 56.250 13.050 57.610 13.100 ;
        RECT 3.550 13.100 56.110 13.110 ;
        RECT 59.825 13.050 63.805 13.110 ;
        RECT 66.790 13.060 92.100 13.110 ;
        RECT 3.550 13.110 92.100 13.710 ;
        RECT 74.860 13.710 78.240 13.720 ;
        RECT 80.270 13.710 82.340 13.720 ;
        RECT 82.660 13.710 87.000 13.720 ;
        RECT 3.550 13.710 4.910 13.760 ;
        RECT 5.895 13.710 7.255 13.760 ;
        RECT 7.995 13.710 9.355 13.760 ;
        RECT 19.030 13.710 20.390 13.760 ;
        RECT 80.270 13.720 87.000 13.760 ;
        RECT 44.615 13.710 68.150 13.770 ;
        RECT 69.340 13.710 73.720 13.770 ;
        RECT 74.860 13.720 78.630 13.770 ;
        RECT 78.660 13.710 80.040 13.770 ;
        RECT 80.960 13.760 84.940 13.770 ;
        RECT 85.390 13.760 87.000 13.770 ;
        RECT 87.565 13.710 87.865 13.770 ;
        RECT 87.920 13.710 89.300 13.770 ;
        RECT 89.450 13.720 90.810 13.770 ;
        RECT 21.375 13.710 37.370 14.370 ;
        RECT 21.375 14.370 22.735 14.420 ;
        RECT 23.175 14.370 37.370 14.420 ;
        RECT 44.615 13.770 90.810 14.420 ;
        RECT 23.175 14.420 36.525 14.430 ;
        RECT 42.940 14.380 44.300 14.430 ;
        RECT 23.175 14.430 44.300 15.030 ;
        RECT 44.975 14.420 90.810 15.030 ;
        RECT 28.735 15.030 44.300 15.040 ;
        RECT 23.175 15.030 24.535 15.080 ;
        RECT 28.735 15.040 44.645 15.080 ;
        RECT 44.975 15.030 47.045 15.080 ;
        RECT 77.270 15.030 78.630 15.080 ;
        RECT 81.330 15.030 82.690 15.080 ;
        RECT 85.390 15.030 86.750 15.080 ;
        RECT 89.450 15.030 90.810 15.080 ;
        RECT 29.340 15.080 44.645 15.090 ;
        RECT 45.665 15.080 47.045 15.090 ;
        RECT 47.430 15.030 75.415 15.090 ;
        RECT 29.340 15.090 75.415 15.690 ;
        RECT 29.350 15.690 54.455 15.740 ;
        RECT 74.055 15.690 75.415 15.740 ;
        RECT 29.540 15.740 54.455 15.750 ;
        RECT 56.310 15.690 69.855 15.750 ;
        RECT 29.590 15.750 69.855 16.350 ;
        RECT 60.370 16.350 61.730 16.400 ;
        RECT 64.345 16.350 69.855 16.400 ;
        RECT 29.590 16.350 32.970 16.400 ;
        RECT 30.885 16.400 32.970 16.410 ;
        RECT 33.750 16.350 35.530 16.410 ;
        RECT 36.730 16.350 58.515 16.410 ;
        RECT 64.345 16.400 68.325 17.010 ;
        RECT 33.750 16.410 58.515 17.010 ;
        RECT 57.155 17.010 58.515 17.060 ;
        RECT 64.490 17.010 65.850 17.060 ;
        RECT 66.820 17.010 68.180 17.060 ;
        RECT 33.750 17.010 50.395 17.070 ;
        RECT 52.250 17.020 53.610 17.070 ;
        RECT 55.465 17.020 56.825 17.070 ;
        RECT 33.750 17.070 56.825 17.670 ;
        RECT 35.900 17.670 40.585 17.720 ;
        RECT 0.090 17.680 1.450 17.730 ;
        RECT 5.650 17.680 7.010 17.730 ;
        RECT 11.055 17.680 12.415 17.730 ;
        RECT 14.885 17.680 16.245 17.730 ;
        RECT 17.615 17.680 18.975 17.730 ;
        RECT 20.830 17.680 22.190 17.730 ;
        RECT 26.390 17.680 27.750 17.730 ;
        RECT 29.590 16.400 30.870 17.730 ;
        RECT 31.690 16.410 32.970 17.730 ;
        RECT 33.750 17.670 35.530 17.730 ;
        RECT 35.900 17.720 39.880 17.730 ;
        RECT 40.915 17.670 56.825 17.730 ;
        RECT 71.710 17.680 73.070 17.730 ;
        RECT 0.090 17.730 73.070 18.390 ;
        RECT 73.210 18.340 74.570 18.390 ;
        RECT 0.090 18.390 74.570 18.990 ;
        RECT 0.090 18.990 1.450 19.040 ;
        RECT 1.590 18.990 74.570 19.650 ;
        RECT 1.590 19.650 2.950 19.700 ;
        RECT 7.150 19.650 8.510 19.700 ;
        RECT 8.710 19.650 10.070 19.700 ;
        RECT 10.210 19.650 13.415 19.700 ;
        RECT 13.870 19.650 15.230 19.700 ;
        RECT 15.400 19.650 18.235 19.700 ;
        RECT 22.330 19.650 23.690 19.700 ;
        RECT 27.890 19.650 29.250 19.700 ;
        RECT 40.070 19.650 41.430 19.700 ;
        RECT 44.130 19.650 45.490 19.700 ;
        RECT 65.990 19.650 67.350 19.700 ;
        RECT 73.210 19.650 74.570 19.700 ;
        RECT 13.730 32.890 15.110 32.940 ;
        RECT 29.590 19.650 30.870 32.940 ;
        RECT 31.690 19.650 32.970 32.940 ;
        RECT 33.750 19.650 35.530 32.940 ;
        RECT 13.730 32.940 35.530 34.220 ;
        RECT 13.730 34.220 15.110 34.270 ;
        RECT 13.730 39.790 15.110 39.840 ;
        RECT 29.590 34.220 30.870 39.840 ;
        RECT 31.690 34.220 32.970 39.840 ;
        RECT 33.750 34.220 35.030 39.840 ;
        RECT 13.730 39.840 35.030 41.120 ;
        RECT 13.730 41.120 15.110 41.170 ;
        RECT 13.730 46.690 15.110 46.740 ;
        RECT 29.590 41.120 30.870 46.740 ;
        RECT 31.690 41.120 32.970 46.740 ;
        RECT 13.730 46.740 32.970 48.020 ;
        RECT 13.730 48.020 15.110 48.070 ;
        RECT 13.730 53.590 15.110 53.640 ;
        RECT 29.590 48.020 30.870 53.640 ;
        RECT 13.730 53.640 30.870 54.920 ;
        RECT 13.730 54.920 15.110 54.970 ;
        RECT 9.630 60.490 11.010 60.540 ;
        RECT 45.715 19.650 46.995 60.540 ;
        RECT 9.630 60.540 46.995 61.820 ;
        RECT 9.630 61.820 11.010 61.870 ;
        RECT 87.565 15.030 87.865 69.490 ;
        RECT 87.000 69.490 88.380 70.870 ;
        RECT 70.210 51.190 71.590 52.570 ;
        RECT 70.210 58.090 71.590 59.470 ;
        RECT 70.210 44.290 71.590 45.670 ;
        RECT 66.820 71.250 68.180 78.590 ;
        RECT 46.850 83.650 48.230 85.030 ;
        RECT 48.850 83.650 50.230 85.030 ;
        RECT 50.850 83.650 52.230 85.030 ;
        RECT 52.850 83.650 54.230 85.030 ;
        RECT 54.850 83.650 56.230 85.030 ;
        RECT 56.850 83.650 58.230 85.030 ;
        RECT 58.850 83.650 60.230 85.030 ;
        RECT 60.850 83.650 62.230 85.030 ;
        RECT 62.850 83.650 64.230 85.030 ;
        RECT 64.850 83.650 66.230 85.030 ;
        RECT 66.850 83.650 68.230 85.030 ;
        RECT 68.850 83.650 70.230 85.030 ;
        RECT 70.850 83.650 72.230 85.030 ;
        RECT 72.850 83.650 74.230 85.030 ;
        RECT 74.850 83.650 76.230 85.030 ;
        RECT 76.850 83.650 78.230 85.030 ;
        RECT 78.850 83.650 80.230 85.030 ;
        RECT 80.850 83.650 82.230 85.030 ;
        RECT 82.850 83.650 84.230 85.030 ;
        RECT 84.850 83.650 86.230 85.030 ;
        RECT 86.850 83.650 88.230 85.030 ;
        RECT 88.850 83.650 90.230 85.030 ;
        RECT 90.850 83.650 92.230 85.030 ;
        RECT 92.850 83.650 94.230 85.030 ;
        RECT -1.150 83.650 0.230 85.030 ;
        RECT 0.850 83.650 2.230 85.030 ;
        RECT 2.850 83.650 4.230 85.030 ;
        RECT 4.850 83.650 6.230 85.030 ;
        RECT 6.850 83.650 8.230 85.030 ;
        RECT 8.850 83.650 10.230 85.030 ;
        RECT 10.850 83.650 12.230 85.030 ;
        RECT 12.850 83.650 14.230 85.030 ;
        RECT 14.850 83.650 16.230 85.030 ;
        RECT 16.850 83.650 18.230 85.030 ;
        RECT 18.850 83.650 20.230 85.030 ;
        RECT 20.850 83.650 22.230 85.030 ;
        RECT 22.850 83.650 24.230 85.030 ;
        RECT 24.850 83.650 26.230 85.030 ;
        RECT 26.850 83.650 28.230 85.030 ;
        RECT 28.850 83.650 30.230 85.030 ;
        RECT 30.850 83.650 32.230 85.030 ;
        RECT 32.850 83.650 34.230 85.030 ;
        RECT 34.850 83.650 36.230 85.030 ;
        RECT 36.850 83.650 38.230 85.030 ;
        RECT 38.850 83.650 40.230 85.030 ;
        RECT 40.850 83.650 42.230 85.030 ;
        RECT 42.850 83.650 44.230 85.030 ;
        RECT 44.850 83.650 46.230 85.030 ;
        RECT 0.850 -0.240 2.230 1.140 ;
        RECT 2.850 -0.240 4.230 1.140 ;
        RECT 4.850 -0.240 6.230 1.140 ;
        RECT 6.850 -0.240 8.230 1.140 ;
        RECT 8.850 -0.240 10.230 1.140 ;
        RECT 10.850 -0.240 12.230 1.140 ;
        RECT 12.850 -0.240 14.230 1.140 ;
        RECT 14.850 -0.240 16.230 1.140 ;
        RECT 16.850 -0.240 18.230 1.140 ;
        RECT 18.850 -0.240 20.230 1.140 ;
        RECT 20.850 -0.240 22.230 1.140 ;
        RECT 22.850 -0.240 24.230 1.140 ;
        RECT 24.850 -0.240 26.230 1.140 ;
        RECT 26.850 -0.240 28.230 1.140 ;
        RECT 28.850 -0.240 30.230 1.140 ;
        RECT 30.850 -0.240 32.230 1.140 ;
        RECT 32.850 -0.240 34.230 1.140 ;
        RECT 34.850 -0.240 36.230 1.140 ;
        RECT 36.850 -0.240 38.230 1.140 ;
        RECT 38.850 -0.240 40.230 1.140 ;
        RECT 40.850 -0.240 42.230 1.140 ;
        RECT 42.850 -0.240 44.230 1.140 ;
        RECT 44.850 -0.240 46.230 1.140 ;
        RECT 37.560 2.450 38.920 6.040 ;
        RECT 42.940 2.450 44.300 6.040 ;
        RECT -1.150 -0.240 0.230 1.140 ;
        RECT 52.850 -0.240 54.230 1.140 ;
        RECT 54.850 -0.240 56.230 1.140 ;
        RECT 56.850 -0.240 58.230 1.140 ;
        RECT 58.850 -0.240 60.230 1.140 ;
        RECT 60.850 -0.240 62.230 1.140 ;
        RECT 62.850 -0.240 64.230 1.140 ;
        RECT 64.850 -0.240 66.230 1.140 ;
        RECT 66.850 -0.240 68.230 1.140 ;
        RECT 68.850 -0.240 70.230 1.140 ;
        RECT 70.850 -0.240 72.230 1.140 ;
        RECT 72.850 -0.240 74.230 1.140 ;
        RECT 74.850 -0.240 76.230 1.140 ;
        RECT 76.850 -0.240 78.230 1.140 ;
        RECT 78.850 -0.240 80.230 1.140 ;
        RECT 80.850 -0.240 82.230 1.140 ;
        RECT 82.850 -0.240 84.230 1.140 ;
        RECT 84.850 -0.240 86.230 1.140 ;
        RECT 86.850 -0.240 88.230 1.140 ;
        RECT 88.850 -0.240 90.230 1.140 ;
        RECT 90.850 -0.240 92.230 1.140 ;
        RECT 92.850 -0.240 94.230 1.140 ;
        RECT 46.850 -0.240 48.230 1.140 ;
        RECT 48.850 -0.240 50.230 1.140 ;
        RECT 62.300 3.700 63.660 8.540 ;
        RECT 70.210 37.390 71.590 38.770 ;
        RECT 50.850 -0.240 52.230 1.140 ;
      LAYER Via3 ;
        RECT 74.015 12.220 74.415 12.800 ;
        RECT 80.115 12.220 80.515 12.800 ;
        RECT 75.350 12.880 75.750 13.280 ;
        RECT 81.450 12.880 81.850 13.280 ;
        RECT 72.830 12.880 73.230 13.360 ;
        RECT 76.250 12.880 79.550 13.360 ;
        RECT 88.325 10.530 92.105 14.310 ;
        RECT 33.700 13.050 35.580 13.170 ;
        RECT 32.285 13.170 36.065 13.230 ;
        RECT 4.285 13.230 36.065 16.950 ;
        RECT 4.285 16.950 35.530 18.310 ;
        RECT 4.285 18.310 8.265 22.930 ;
        RECT 29.590 18.310 35.530 22.930 ;
        RECT 4.285 22.930 35.530 26.910 ;
        RECT 13.730 32.890 15.110 32.940 ;
        RECT 29.590 26.910 30.870 32.940 ;
        RECT 31.690 26.910 32.970 32.940 ;
        RECT 33.750 26.910 35.530 32.940 ;
        RECT 13.730 32.940 35.530 34.220 ;
        RECT 13.730 34.220 15.110 34.270 ;
        RECT 13.730 39.790 15.110 39.840 ;
        RECT 29.590 34.220 30.870 39.840 ;
        RECT 31.690 34.220 32.970 39.840 ;
        RECT 33.750 34.220 35.030 39.840 ;
        RECT 13.730 39.840 35.030 41.120 ;
        RECT 13.730 41.120 15.110 41.170 ;
        RECT 13.730 46.690 15.110 46.740 ;
        RECT 29.590 41.120 30.870 46.740 ;
        RECT 31.690 41.120 32.970 46.740 ;
        RECT 13.730 46.740 32.970 48.020 ;
        RECT 13.730 48.020 15.110 48.070 ;
        RECT 13.730 53.590 15.110 53.640 ;
        RECT 29.590 48.020 30.870 53.640 ;
        RECT 13.730 53.640 30.870 54.920 ;
        RECT 13.730 54.920 15.110 54.970 ;
        RECT 41.725 9.930 71.505 15.010 ;
        RECT 41.725 15.010 47.045 15.090 ;
        RECT 41.725 15.090 45.705 19.630 ;
        RECT 45.715 15.090 46.995 19.630 ;
        RECT 67.325 15.010 71.505 19.630 ;
        RECT 41.725 19.630 71.505 23.610 ;
        RECT 9.630 60.490 11.010 60.540 ;
        RECT 45.715 23.610 46.995 60.540 ;
        RECT 9.630 60.540 46.995 61.820 ;
        RECT 9.630 61.820 11.010 61.870 ;
        RECT 87.515 12.220 87.915 12.620 ;
        RECT 87.565 12.620 87.865 69.980 ;
      LAYER Via4 ;
        RECT 41.725 9.930 71.505 10.420 ;
        RECT 6.275 10.420 90.815 10.530 ;
        RECT 6.275 10.530 92.105 11.620 ;
        RECT 6.275 11.620 7.475 13.230 ;
        RECT 32.285 13.170 36.065 13.230 ;
        RECT 88.325 11.620 92.105 14.310 ;
        RECT 4.285 13.230 36.065 14.460 ;
        RECT 41.725 11.620 71.505 14.460 ;
        RECT 4.285 14.460 71.505 15.660 ;
        RECT 4.285 15.660 36.065 16.950 ;
        RECT 41.725 15.660 71.505 23.610 ;
        RECT 4.285 16.950 34.065 26.910 ;
      LAYER Metal1 ;
        RECT 0.910 1.650 1.730 2.150 ;
        RECT 0.910 2.150 1.760 2.870 ;
        RECT 0.000 2.870 1.760 2.880 ;
        RECT -0.160 2.880 1.760 3.690 ;
        RECT 0.225 3.690 0.915 12.020 ;
        RECT 1.070 3.690 1.760 12.020 ;
        RECT 0.170 12.020 0.970 12.820 ;
        RECT 1.015 12.020 1.815 12.820 ;
        RECT 3.660 6.870 4.960 6.880 ;
        RECT 3.500 6.880 4.960 7.690 ;
        RECT 3.885 7.690 4.575 12.680 ;
        RECT 3.830 12.680 4.630 13.480 ;
        RECT 6.070 1.650 6.890 4.150 ;
        RECT 6.070 4.150 6.920 6.870 ;
        RECT 5.000 6.870 6.920 7.690 ;
        RECT 5.385 7.690 6.075 12.020 ;
        RECT 6.230 7.690 6.920 12.680 ;
        RECT 5.330 12.020 6.130 12.820 ;
        RECT 6.175 12.680 6.975 13.480 ;
        RECT 19.140 6.870 20.440 6.880 ;
        RECT 18.980 6.880 20.440 7.690 ;
        RECT 19.365 7.690 20.055 12.680 ;
        RECT 19.310 12.680 20.110 13.480 ;
        RECT 24.300 6.870 25.600 6.880 ;
        RECT 24.140 6.880 25.600 7.690 ;
        RECT 24.525 7.690 25.215 12.680 ;
        RECT 24.470 12.680 25.270 13.480 ;
        RECT 54.860 6.870 56.160 6.880 ;
        RECT 54.700 6.880 56.160 7.690 ;
        RECT 55.085 7.690 55.775 12.680 ;
        RECT 55.030 12.680 55.830 13.480 ;
        RECT 60.080 6.870 61.380 6.880 ;
        RECT 59.920 6.880 61.380 7.690 ;
        RECT 60.305 7.690 60.995 12.680 ;
        RECT 60.250 12.680 61.050 13.480 ;
        RECT 70.560 3.870 72.700 3.880 ;
        RECT 70.400 3.880 72.860 4.690 ;
        RECT 71.285 4.690 71.975 12.680 ;
        RECT 71.230 12.680 72.030 13.480 ;
        RECT 75.220 3.870 77.360 3.880 ;
        RECT 75.060 3.880 77.520 4.690 ;
        RECT 75.945 4.690 76.635 12.680 ;
        RECT 75.890 12.680 76.690 13.480 ;
        RECT 79.880 3.870 82.020 3.880 ;
        RECT 79.720 3.880 82.180 4.690 ;
        RECT 80.605 4.690 81.295 12.680 ;
        RECT 80.550 12.680 81.350 13.480 ;
        RECT 84.540 3.870 86.680 3.880 ;
        RECT 84.380 3.880 86.840 4.690 ;
        RECT 85.265 4.690 85.955 12.680 ;
        RECT 85.210 12.680 86.010 13.480 ;
        RECT 21.550 1.650 22.370 4.150 ;
        RECT 21.550 4.150 22.400 6.870 ;
        RECT 20.480 6.870 22.400 7.690 ;
        RECT 20.865 7.690 21.555 12.020 ;
        RECT 20.810 12.020 21.610 12.820 ;
        RECT 21.710 7.690 22.400 13.340 ;
        RECT 21.655 13.340 22.455 14.140 ;
        RECT 26.710 1.650 27.530 4.150 ;
        RECT 26.710 4.150 27.560 6.870 ;
        RECT 25.640 6.870 27.560 7.690 ;
        RECT 26.025 7.690 26.715 12.020 ;
        RECT 25.970 12.020 26.770 12.820 ;
        RECT 26.870 7.690 27.560 13.340 ;
        RECT 26.815 13.340 27.615 14.140 ;
        RECT 67.810 1.650 68.630 2.150 ;
        RECT 67.810 2.150 68.660 2.870 ;
        RECT 66.900 2.870 68.660 2.880 ;
        RECT 66.740 2.880 68.660 3.690 ;
        RECT 67.970 3.690 68.660 12.020 ;
        RECT 67.915 12.020 68.715 12.820 ;
        RECT 67.125 3.690 67.815 13.340 ;
        RECT 67.070 13.340 67.870 14.140 ;
        RECT 50.610 1.650 51.430 2.650 ;
        RECT 52.110 1.650 52.930 2.650 ;
        RECT 50.580 2.650 51.430 3.870 ;
        RECT 52.110 2.650 52.960 3.870 ;
        RECT 50.580 3.870 52.960 4.690 ;
        RECT 50.580 4.690 51.270 13.340 ;
        RECT 52.270 4.690 52.960 14.000 ;
        RECT 50.525 13.340 51.325 14.140 ;
        RECT 51.425 4.690 52.115 14.660 ;
        RECT 52.215 14.000 53.015 14.800 ;
        RECT 51.370 14.660 52.170 15.460 ;
        RECT 64.150 1.650 64.970 4.150 ;
        RECT 62.570 1.650 63.390 6.870 ;
        RECT 64.150 4.150 65.000 6.870 ;
        RECT 61.420 6.870 65.000 7.110 ;
        RECT 61.420 7.110 62.880 7.460 ;
        RECT 63.080 7.110 65.000 7.460 ;
        RECT 61.420 7.460 65.000 7.690 ;
        RECT 62.580 7.690 63.380 8.260 ;
        RECT 61.805 7.690 62.495 12.020 ;
        RECT 62.635 8.260 63.325 12.680 ;
        RECT 61.750 12.020 62.550 12.820 ;
        RECT 62.580 12.680 63.380 13.480 ;
        RECT 63.465 7.690 64.155 14.660 ;
        RECT 64.310 7.690 65.000 14.660 ;
        RECT 63.410 14.660 64.210 15.460 ;
        RECT 64.255 14.660 65.055 15.460 ;
        RECT 32.530 1.650 33.350 5.900 ;
        RECT 34.030 1.650 34.850 5.900 ;
        RECT 32.500 5.900 33.350 10.370 ;
        RECT 34.030 5.900 34.880 10.370 ;
        RECT 32.500 10.370 34.880 11.190 ;
        RECT 32.500 11.190 33.190 13.340 ;
        RECT 33.345 11.190 34.035 13.340 ;
        RECT 32.445 13.340 33.245 14.140 ;
        RECT 33.290 13.340 34.090 14.140 ;
        RECT 34.190 11.190 34.880 16.640 ;
        RECT 34.135 16.640 34.935 17.440 ;
        RECT 13.980 2.870 15.280 2.880 ;
        RECT 13.820 2.880 15.280 3.690 ;
        RECT 14.205 3.690 14.895 18.620 ;
        RECT 14.150 18.620 14.950 19.420 ;
        RECT 13.990 33.150 14.850 34.510 ;
        RECT 70.470 33.150 71.330 36.760 ;
        RECT 13.990 35.400 14.850 39.010 ;
        RECT 70.470 37.650 71.330 39.010 ;
        RECT 13.990 40.050 14.850 41.410 ;
        RECT 70.470 40.050 71.330 43.660 ;
        RECT 13.990 42.300 14.850 45.910 ;
        RECT 70.470 44.550 71.330 45.910 ;
        RECT 13.990 46.950 14.850 48.310 ;
        RECT 70.470 46.950 71.330 50.560 ;
        RECT 13.990 49.200 14.850 52.810 ;
        RECT 70.470 51.450 71.330 52.810 ;
        RECT 13.990 53.850 14.850 55.210 ;
        RECT 70.470 53.850 71.330 57.460 ;
        RECT 13.990 56.100 14.850 59.710 ;
        RECT 70.470 58.350 71.330 59.710 ;
        RECT 9.890 60.750 10.750 62.110 ;
        RECT 9.890 63.000 10.750 66.610 ;
        RECT 9.890 67.500 10.750 71.110 ;
        RECT 0.370 17.960 1.170 18.760 ;
        RECT 0.425 18.760 1.115 72.100 ;
        RECT 0.040 72.100 1.500 72.910 ;
        RECT 0.200 72.910 1.500 72.920 ;
        RECT 5.930 17.960 6.730 18.760 ;
        RECT 5.985 18.760 6.675 72.100 ;
        RECT 5.600 72.100 7.060 72.910 ;
        RECT 5.760 72.910 7.060 72.920 ;
        RECT 21.110 17.960 21.910 18.760 ;
        RECT 21.165 18.760 21.855 72.100 ;
        RECT 20.780 72.100 22.240 72.910 ;
        RECT 20.940 72.910 22.240 72.920 ;
        RECT 26.670 17.960 27.470 18.760 ;
        RECT 26.725 18.760 27.415 72.100 ;
        RECT 26.340 72.100 27.800 72.910 ;
        RECT 26.500 72.910 27.800 72.920 ;
        RECT 64.770 15.980 65.570 16.780 ;
        RECT 64.825 16.780 65.515 72.100 ;
        RECT 64.440 72.100 65.900 72.910 ;
        RECT 64.600 72.910 65.900 72.920 ;
        RECT 71.990 17.960 72.790 18.760 ;
        RECT 72.045 18.760 72.735 72.100 ;
        RECT 71.660 72.100 73.120 72.910 ;
        RECT 71.820 72.910 73.120 72.920 ;
        RECT 2.715 12.020 3.515 12.820 ;
        RECT 1.870 18.620 2.670 19.420 ;
        RECT 1.925 19.420 2.615 72.100 ;
        RECT 2.770 12.820 3.460 72.100 ;
        RECT 1.540 72.100 3.460 72.920 ;
        RECT 2.610 72.920 3.460 78.140 ;
        RECT 2.610 78.140 3.430 83.140 ;
        RECT 8.820 2.870 10.120 2.880 ;
        RECT 8.660 2.880 10.120 3.690 ;
        RECT 9.045 3.690 9.735 12.680 ;
        RECT 8.275 12.680 9.735 13.480 ;
        RECT 8.330 13.480 9.020 18.620 ;
        RECT 9.045 13.480 9.735 18.620 ;
        RECT 7.430 18.620 8.230 19.420 ;
        RECT 8.330 18.620 9.790 19.420 ;
        RECT 8.330 19.420 9.020 60.750 ;
        RECT 8.330 60.750 9.660 62.110 ;
        RECT 8.330 62.110 9.020 63.000 ;
        RECT 8.330 63.000 9.660 64.360 ;
        RECT 8.330 64.360 9.020 65.250 ;
        RECT 8.330 65.250 9.660 66.610 ;
        RECT 8.330 66.610 9.020 67.500 ;
        RECT 8.330 67.500 9.660 68.860 ;
        RECT 8.330 68.860 9.020 69.750 ;
        RECT 8.330 69.750 9.660 71.110 ;
        RECT 7.485 19.420 8.175 72.100 ;
        RECT 8.330 71.110 9.020 72.100 ;
        RECT 7.100 72.100 9.020 72.920 ;
        RECT 8.170 72.920 9.020 78.140 ;
        RECT 8.170 78.140 8.990 83.140 ;
        RECT 11.230 1.650 12.050 2.150 ;
        RECT 11.230 2.150 12.080 2.870 ;
        RECT 10.160 2.870 12.080 3.690 ;
        RECT 11.390 3.690 12.080 17.960 ;
        RECT 10.545 3.690 11.235 18.620 ;
        RECT 11.335 17.960 12.135 18.620 ;
        RECT 11.335 18.620 12.290 18.760 ;
        RECT 10.490 18.620 11.290 19.420 ;
        RECT 11.490 18.760 12.290 19.420 ;
        RECT 12.335 18.620 13.135 19.420 ;
        RECT 12.390 19.420 13.080 33.150 ;
        RECT 12.390 33.150 13.760 34.510 ;
        RECT 12.390 34.510 13.080 35.400 ;
        RECT 12.390 35.400 13.760 36.760 ;
        RECT 12.390 36.760 13.080 37.650 ;
        RECT 12.390 37.650 13.760 39.010 ;
        RECT 12.390 39.010 13.080 40.050 ;
        RECT 12.390 40.050 13.760 41.410 ;
        RECT 12.390 41.410 13.080 42.300 ;
        RECT 12.390 42.300 13.760 43.660 ;
        RECT 12.390 43.660 13.080 44.550 ;
        RECT 12.390 44.550 13.760 45.910 ;
        RECT 12.390 45.910 13.080 46.950 ;
        RECT 12.390 46.950 13.760 48.310 ;
        RECT 12.390 48.310 13.080 49.200 ;
        RECT 12.390 49.200 13.760 50.560 ;
        RECT 12.390 50.560 13.080 51.450 ;
        RECT 12.390 51.450 13.760 52.810 ;
        RECT 12.390 52.810 13.080 53.850 ;
        RECT 12.390 53.850 13.760 55.210 ;
        RECT 12.390 55.210 13.080 56.100 ;
        RECT 12.390 56.100 13.760 57.460 ;
        RECT 12.390 57.460 13.080 58.350 ;
        RECT 12.390 58.350 13.760 59.710 ;
        RECT 11.545 19.420 12.235 80.100 ;
        RECT 12.390 59.710 13.080 80.100 ;
        RECT 11.160 80.100 13.080 80.910 ;
        RECT 11.320 80.910 13.080 80.920 ;
        RECT 12.230 80.920 13.080 82.140 ;
        RECT 12.230 82.140 13.050 83.140 ;
        RECT 16.390 1.650 17.210 2.150 ;
        RECT 16.390 2.150 17.240 2.870 ;
        RECT 15.320 2.870 17.240 3.690 ;
        RECT 15.735 3.690 16.425 17.960 ;
        RECT 15.165 17.960 16.425 18.620 ;
        RECT 16.550 3.690 17.240 18.620 ;
        RECT 17.895 17.960 18.695 18.620 ;
        RECT 15.165 18.620 16.480 18.760 ;
        RECT 16.495 18.620 18.695 18.760 ;
        RECT 15.220 18.760 16.480 19.420 ;
        RECT 16.495 18.760 18.640 19.420 ;
        RECT 15.220 19.420 15.910 72.100 ;
        RECT 17.210 19.420 17.900 72.100 ;
        RECT 17.950 19.420 18.640 72.100 ;
        RECT 15.220 72.100 16.680 72.910 ;
        RECT 15.380 72.910 16.680 72.920 ;
        RECT 16.720 72.100 18.640 72.920 ;
        RECT 17.790 72.920 18.640 78.140 ;
        RECT 17.790 78.140 18.610 83.140 ;
        RECT 23.455 14.000 24.255 14.800 ;
        RECT 22.610 18.620 23.410 19.420 ;
        RECT 22.665 19.420 23.355 72.100 ;
        RECT 23.510 14.800 24.200 72.100 ;
        RECT 22.280 72.100 24.200 72.920 ;
        RECT 23.350 72.920 24.200 78.140 ;
        RECT 23.350 78.140 24.170 83.140 ;
        RECT 28.870 1.650 29.690 5.400 ;
        RECT 30.370 1.650 31.190 5.400 ;
        RECT 28.840 5.400 29.690 9.370 ;
        RECT 30.370 5.400 31.220 9.370 ;
        RECT 28.840 9.370 31.220 10.190 ;
        RECT 28.840 10.190 29.530 13.340 ;
        RECT 28.785 13.340 29.585 14.000 ;
        RECT 29.685 10.190 30.375 14.000 ;
        RECT 28.785 14.000 30.375 14.140 ;
        RECT 29.015 14.140 30.375 14.660 ;
        RECT 29.015 14.660 30.430 14.800 ;
        RECT 30.530 10.190 31.220 15.320 ;
        RECT 29.070 14.800 30.430 15.460 ;
        RECT 30.475 15.320 31.275 16.120 ;
        RECT 28.170 18.620 28.970 19.420 ;
        RECT 28.225 19.420 28.915 72.100 ;
        RECT 29.070 15.460 29.760 72.100 ;
        RECT 27.840 72.100 29.760 72.920 ;
        RECT 28.910 72.920 29.760 78.140 ;
        RECT 28.910 78.140 29.730 83.140 ;
        RECT 31.385 14.000 32.185 14.800 ;
        RECT 32.230 14.660 33.030 15.460 ;
        RECT 33.075 14.660 33.875 15.460 ;
        RECT 31.440 14.800 32.130 81.550 ;
        RECT 32.285 15.460 32.975 81.550 ;
        RECT 33.130 15.460 33.820 81.550 ;
        RECT 31.440 81.550 33.820 82.370 ;
        RECT 31.440 82.370 32.290 82.865 ;
        RECT 32.970 82.370 33.820 82.865 ;
        RECT 31.470 82.865 32.290 83.140 ;
        RECT 32.970 82.865 33.790 83.140 ;
        RECT 39.410 1.650 40.230 2.900 ;
        RECT 37.830 1.650 38.650 4.370 ;
        RECT 39.410 2.900 40.260 4.370 ;
        RECT 36.840 4.370 40.260 4.380 ;
        RECT 36.680 4.380 40.260 4.610 ;
        RECT 36.680 4.610 38.140 4.960 ;
        RECT 38.340 4.610 40.260 4.960 ;
        RECT 36.680 4.960 40.260 5.190 ;
        RECT 37.840 5.190 38.640 5.760 ;
        RECT 38.725 5.190 39.415 12.020 ;
        RECT 38.670 12.020 39.470 12.820 ;
        RECT 37.065 5.190 37.755 13.340 ;
        RECT 36.290 13.340 37.755 14.140 ;
        RECT 35.445 14.000 36.245 14.800 ;
        RECT 36.345 14.140 37.035 15.980 ;
        RECT 37.065 14.140 37.755 15.980 ;
        RECT 39.570 5.190 40.260 15.980 ;
        RECT 39.515 15.980 40.315 16.640 ;
        RECT 36.345 15.980 37.810 16.780 ;
        RECT 39.505 16.640 40.315 16.780 ;
        RECT 37.895 5.760 38.585 17.300 ;
        RECT 39.505 16.780 40.305 17.440 ;
        RECT 37.135 17.300 38.640 18.100 ;
        RECT 41.195 17.300 41.995 18.100 ;
        RECT 40.350 18.620 41.150 19.420 ;
        RECT 39.560 17.440 40.250 72.100 ;
        RECT 40.405 19.420 41.095 72.100 ;
        RECT 41.250 18.100 41.940 72.100 ;
        RECT 39.560 72.100 41.940 72.920 ;
        RECT 39.560 72.920 40.410 78.140 ;
        RECT 41.090 72.920 41.940 78.140 ;
        RECT 35.500 14.800 36.190 81.600 ;
        RECT 36.345 16.780 37.035 81.600 ;
        RECT 37.190 18.100 37.880 81.600 ;
        RECT 35.500 81.600 37.880 82.420 ;
        RECT 35.500 82.420 36.350 82.890 ;
        RECT 37.030 82.420 37.880 82.890 ;
        RECT 35.530 82.890 36.350 83.140 ;
        RECT 37.030 82.890 37.850 83.140 ;
        RECT 39.590 78.140 40.410 83.140 ;
        RECT 41.090 78.140 41.910 83.140 ;
        RECT 44.790 1.650 45.610 2.900 ;
        RECT 43.210 1.650 44.030 4.370 ;
        RECT 44.790 2.900 45.640 4.370 ;
        RECT 42.220 4.370 45.640 4.380 ;
        RECT 42.060 4.380 45.640 4.610 ;
        RECT 42.060 4.610 43.520 4.960 ;
        RECT 43.720 4.610 45.640 4.960 ;
        RECT 42.060 4.960 45.640 5.190 ;
        RECT 43.220 5.190 44.020 5.760 ;
        RECT 44.105 5.190 44.795 12.020 ;
        RECT 44.050 12.020 44.850 12.820 ;
        RECT 44.950 5.190 45.640 13.340 ;
        RECT 44.895 13.340 45.695 14.000 ;
        RECT 44.895 14.000 46.055 14.140 ;
        RECT 43.275 5.760 43.965 14.660 ;
        RECT 45.255 14.140 46.055 14.800 ;
        RECT 43.220 14.660 44.020 15.320 ;
        RECT 43.220 15.320 44.365 15.460 ;
        RECT 42.445 5.190 43.135 15.980 ;
        RECT 43.565 15.460 44.365 16.120 ;
        RECT 42.390 15.980 43.190 16.780 ;
        RECT 44.410 18.620 45.210 19.420 ;
        RECT 43.620 16.120 44.310 72.100 ;
        RECT 44.465 19.420 45.155 72.100 ;
        RECT 45.310 14.800 46.000 72.100 ;
        RECT 43.620 72.100 46.000 72.920 ;
        RECT 43.620 72.920 44.470 78.140 ;
        RECT 45.150 72.920 46.000 78.140 ;
        RECT 43.650 78.140 44.470 83.140 ;
        RECT 45.150 78.140 45.970 83.140 ;
        RECT 46.950 1.650 47.770 2.650 ;
        RECT 48.450 1.650 49.270 2.650 ;
        RECT 46.920 2.650 47.770 3.870 ;
        RECT 48.450 2.650 49.400 3.870 ;
        RECT 46.920 3.870 49.400 4.690 ;
        RECT 47.765 4.690 48.455 14.660 ;
        RECT 47.710 14.660 48.510 15.460 ;
        RECT 46.920 4.690 47.610 15.980 ;
        RECT 48.710 4.690 49.400 16.640 ;
        RECT 46.865 15.980 47.665 16.780 ;
        RECT 48.710 16.640 50.115 17.300 ;
        RECT 48.140 17.300 50.115 17.440 ;
        RECT 48.140 17.440 50.060 18.100 ;
        RECT 48.140 18.100 48.830 77.100 ;
        RECT 49.370 18.100 50.060 77.100 ;
        RECT 48.140 77.100 50.060 77.910 ;
        RECT 48.300 77.910 50.060 77.920 ;
        RECT 49.210 77.920 50.060 80.640 ;
        RECT 49.210 80.640 50.030 83.140 ;
        RECT 53.375 15.320 54.175 16.120 ;
        RECT 52.530 17.300 53.330 18.100 ;
        RECT 52.585 18.100 53.275 77.100 ;
        RECT 53.430 16.120 54.120 77.100 ;
        RECT 52.200 77.100 54.120 77.910 ;
        RECT 52.360 77.910 54.120 77.920 ;
        RECT 53.270 77.920 54.120 80.640 ;
        RECT 53.270 80.640 54.090 83.140 ;
        RECT 57.270 1.650 58.090 4.150 ;
        RECT 57.270 4.150 58.120 6.870 ;
        RECT 56.200 6.870 58.120 7.690 ;
        RECT 56.585 7.690 57.275 12.020 ;
        RECT 56.530 12.020 57.330 12.820 ;
        RECT 57.430 7.690 58.120 15.320 ;
        RECT 56.590 15.320 58.175 15.980 ;
        RECT 56.590 15.980 58.235 16.120 ;
        RECT 57.435 16.120 58.235 16.780 ;
        RECT 55.745 17.300 56.545 18.100 ;
        RECT 55.800 18.100 56.490 78.100 ;
        RECT 56.645 16.120 57.335 78.100 ;
        RECT 57.490 16.780 58.180 78.100 ;
        RECT 55.800 78.100 58.180 78.920 ;
        RECT 55.800 78.920 56.650 81.140 ;
        RECT 57.330 78.920 58.180 81.140 ;
        RECT 55.830 81.140 56.650 83.140 ;
        RECT 57.330 81.140 58.150 83.140 ;
        RECT 61.495 13.340 62.295 14.140 ;
        RECT 59.805 14.000 60.605 14.800 ;
        RECT 60.650 15.320 61.450 16.120 ;
        RECT 59.860 14.800 60.550 78.100 ;
        RECT 60.705 16.120 61.395 78.100 ;
        RECT 61.550 14.140 62.240 78.100 ;
        RECT 59.860 78.100 62.240 78.920 ;
        RECT 59.860 78.920 60.710 81.140 ;
        RECT 61.390 78.920 62.240 81.140 ;
        RECT 59.890 81.140 60.710 83.140 ;
        RECT 61.390 81.140 62.210 83.140 ;
        RECT 67.930 15.320 68.730 16.120 ;
        RECT 68.775 15.320 69.575 16.120 ;
        RECT 67.100 15.980 67.900 16.780 ;
        RECT 66.270 18.620 67.070 19.420 ;
        RECT 67.155 16.780 67.845 71.530 ;
        RECT 66.325 19.420 67.015 72.100 ;
        RECT 67.100 71.530 67.900 72.100 ;
        RECT 67.985 16.120 68.675 72.100 ;
        RECT 68.830 16.120 69.520 72.100 ;
        RECT 65.940 72.100 69.520 72.330 ;
        RECT 65.940 72.330 67.400 72.680 ;
        RECT 67.600 72.330 69.520 72.680 ;
        RECT 65.940 72.680 69.520 72.920 ;
        RECT 68.670 72.920 69.520 78.140 ;
        RECT 67.090 72.920 67.910 83.140 ;
        RECT 68.670 78.140 69.490 83.140 ;
        RECT 74.335 14.660 75.135 15.460 ;
        RECT 73.490 18.620 74.290 19.420 ;
        RECT 73.545 19.420 74.235 72.100 ;
        RECT 74.390 15.460 75.080 72.100 ;
        RECT 73.160 72.100 75.080 72.920 ;
        RECT 74.230 72.920 75.080 78.140 ;
        RECT 74.230 78.140 75.050 83.140 ;
        RECT 78.395 12.020 79.195 12.820 ;
        RECT 77.550 14.000 78.350 14.800 ;
        RECT 77.605 14.800 78.295 81.100 ;
        RECT 78.450 12.820 79.140 81.100 ;
        RECT 77.220 81.100 79.140 81.910 ;
        RECT 77.380 81.910 79.140 81.920 ;
        RECT 78.290 81.920 79.140 82.640 ;
        RECT 78.290 82.640 79.110 83.140 ;
        RECT 82.455 12.020 83.255 12.820 ;
        RECT 81.610 14.000 82.410 14.800 ;
        RECT 81.665 14.800 82.355 81.100 ;
        RECT 82.510 12.820 83.200 81.100 ;
        RECT 81.280 81.100 83.200 81.910 ;
        RECT 81.440 81.910 83.200 81.920 ;
        RECT 82.350 81.920 83.200 82.640 ;
        RECT 82.350 82.640 83.170 83.140 ;
        RECT 86.515 12.020 87.315 12.820 ;
        RECT 85.670 14.000 86.470 14.800 ;
        RECT 86.570 12.820 87.260 60.750 ;
        RECT 86.570 60.750 88.120 64.360 ;
        RECT 86.570 64.360 87.260 65.250 ;
        RECT 86.570 65.250 88.120 68.860 ;
        RECT 86.570 68.860 87.260 69.750 ;
        RECT 86.570 69.750 88.120 71.110 ;
        RECT 85.725 14.800 86.415 81.100 ;
        RECT 86.570 71.110 87.260 81.100 ;
        RECT 85.340 81.100 87.260 81.910 ;
        RECT 85.500 81.910 87.260 81.920 ;
        RECT 86.410 81.920 87.260 82.640 ;
        RECT 86.410 82.640 87.230 83.140 ;
        RECT 90.575 12.020 91.375 12.820 ;
        RECT 89.730 14.000 90.530 14.800 ;
        RECT 89.785 14.800 90.475 81.100 ;
        RECT 90.630 12.820 91.320 81.100 ;
        RECT 89.400 81.100 91.320 81.910 ;
        RECT 89.560 81.910 91.320 81.920 ;
        RECT 90.470 81.920 91.320 82.640 ;
        RECT 90.470 82.640 91.290 83.140 ;
      LAYER Metal2 ;
        RECT 68.325 11.730 69.705 11.740 ;
        RECT 87.025 11.730 88.405 11.740 ;
        RECT 89.525 11.730 90.905 11.740 ;
        RECT -0.110 11.740 2.095 11.790 ;
        RECT 2.435 11.740 3.795 11.790 ;
        RECT 5.050 11.740 6.410 11.790 ;
        RECT 20.530 11.740 21.890 11.790 ;
        RECT 25.690 11.740 27.050 11.790 ;
        RECT 38.390 11.740 39.750 11.790 ;
        RECT 43.770 11.740 45.130 11.790 ;
        RECT 56.250 11.740 57.610 11.790 ;
        RECT 61.470 11.740 62.830 11.790 ;
        RECT 67.635 11.740 69.705 11.790 ;
        RECT 73.525 11.730 74.905 11.790 ;
        RECT 78.115 11.740 79.475 11.790 ;
        RECT 79.625 11.730 81.005 11.790 ;
        RECT 82.175 11.740 83.535 11.790 ;
        RECT 86.235 11.740 88.405 11.790 ;
        RECT 89.525 11.740 91.655 11.790 ;
        RECT -0.110 11.790 62.830 12.400 ;
        RECT -0.110 12.400 63.660 12.450 ;
        RECT 67.635 11.790 91.655 12.450 ;
        RECT -0.110 12.450 63.805 13.050 ;
        RECT 67.635 12.450 92.100 13.060 ;
        RECT -0.110 13.050 2.095 13.100 ;
        RECT 2.435 13.050 56.110 13.100 ;
        RECT 56.250 13.050 57.610 13.100 ;
        RECT 3.550 13.100 56.110 13.110 ;
        RECT 59.825 13.050 63.805 13.110 ;
        RECT 66.790 13.060 92.100 13.110 ;
        RECT 3.550 13.110 92.100 13.710 ;
        RECT 74.860 13.710 78.240 13.720 ;
        RECT 80.270 13.710 82.340 13.720 ;
        RECT 82.660 13.710 87.000 13.720 ;
        RECT 3.550 13.710 4.910 13.760 ;
        RECT 5.895 13.710 7.255 13.760 ;
        RECT 7.995 13.710 9.355 13.760 ;
        RECT 19.030 13.710 20.390 13.760 ;
        RECT 80.270 13.720 87.000 13.760 ;
        RECT 44.615 13.710 68.150 13.770 ;
        RECT 69.340 13.710 73.720 13.770 ;
        RECT 74.860 13.720 78.630 13.770 ;
        RECT 78.660 13.710 80.040 13.770 ;
        RECT 80.960 13.760 84.940 13.770 ;
        RECT 85.390 13.760 87.000 13.770 ;
        RECT 87.920 13.710 89.300 13.770 ;
        RECT 89.450 13.720 90.810 13.770 ;
        RECT 21.375 13.710 37.370 14.370 ;
        RECT 21.375 14.370 22.735 14.420 ;
        RECT 23.175 14.370 37.370 14.420 ;
        RECT 44.615 13.770 90.810 14.420 ;
        RECT 23.175 14.420 36.525 14.430 ;
        RECT 42.940 14.380 44.300 14.430 ;
        RECT 23.175 14.430 44.300 15.030 ;
        RECT 44.975 14.420 90.810 15.030 ;
        RECT 28.735 15.030 44.300 15.040 ;
        RECT 23.175 15.030 24.535 15.080 ;
        RECT 28.735 15.040 44.645 15.080 ;
        RECT 44.975 15.030 47.045 15.080 ;
        RECT 77.270 15.030 78.630 15.080 ;
        RECT 81.330 15.030 82.690 15.080 ;
        RECT 85.390 15.030 86.750 15.080 ;
        RECT 89.450 15.030 90.810 15.080 ;
        RECT 29.340 15.080 44.645 15.090 ;
        RECT 45.665 15.080 47.045 15.090 ;
        RECT 47.430 15.030 75.415 15.090 ;
        RECT 29.340 15.090 75.415 15.690 ;
        RECT 29.350 15.690 54.455 15.740 ;
        RECT 74.055 15.690 75.415 15.740 ;
        RECT 29.540 15.740 54.455 15.750 ;
        RECT 56.310 15.690 69.855 15.750 ;
        RECT 30.195 15.750 69.855 16.350 ;
        RECT 30.195 16.350 32.265 16.400 ;
        RECT 60.370 16.350 61.730 16.400 ;
        RECT 64.345 16.350 69.855 16.400 ;
        RECT 30.885 16.400 32.265 16.410 ;
        RECT 33.855 16.360 35.215 16.410 ;
        RECT 36.730 16.350 58.515 16.410 ;
        RECT 64.345 16.400 68.325 17.010 ;
        RECT 33.855 16.410 58.515 17.010 ;
        RECT 57.155 17.010 58.515 17.060 ;
        RECT 64.490 17.010 65.850 17.060 ;
        RECT 66.820 17.010 68.180 17.060 ;
        RECT 33.855 17.010 50.395 17.070 ;
        RECT 52.250 17.020 53.610 17.070 ;
        RECT 55.465 17.020 56.825 17.070 ;
        RECT 33.855 17.070 56.825 17.670 ;
        RECT 33.855 17.670 35.215 17.720 ;
        RECT 35.900 17.670 40.585 17.720 ;
        RECT 0.090 17.680 1.450 17.730 ;
        RECT 5.650 17.680 7.010 17.730 ;
        RECT 11.055 17.680 12.415 17.730 ;
        RECT 14.885 17.680 16.245 17.730 ;
        RECT 17.615 17.680 18.975 17.730 ;
        RECT 20.830 17.680 22.190 17.730 ;
        RECT 26.390 17.680 27.750 17.730 ;
        RECT 35.900 17.720 39.880 17.730 ;
        RECT 40.915 17.670 56.825 17.730 ;
        RECT 71.710 17.680 73.070 17.730 ;
        RECT 0.090 17.730 73.070 18.390 ;
        RECT 73.210 18.340 74.570 18.390 ;
        RECT 0.090 18.390 74.570 18.990 ;
        RECT 0.090 18.990 1.450 19.040 ;
        RECT 1.590 18.990 74.570 19.650 ;
        RECT 1.590 19.650 2.950 19.700 ;
        RECT 7.150 19.650 8.510 19.700 ;
        RECT 8.710 19.650 10.070 19.700 ;
        RECT 10.210 19.650 13.415 19.700 ;
        RECT 13.870 19.650 15.230 19.700 ;
        RECT 15.400 19.650 18.235 19.700 ;
        RECT 22.330 19.650 23.690 19.700 ;
        RECT 27.890 19.650 29.250 19.700 ;
        RECT 40.070 19.650 41.430 19.700 ;
        RECT 44.130 19.650 45.490 19.700 ;
        RECT 65.990 19.650 67.350 19.700 ;
        RECT 73.210 19.650 74.570 19.700 ;
        RECT 70.210 44.290 71.590 45.670 ;
        RECT 70.210 51.190 71.590 52.570 ;
        RECT 70.210 58.090 71.590 59.470 ;
        RECT 87.000 69.490 88.380 70.870 ;
        RECT 66.820 71.250 68.180 78.590 ;
        RECT 46.850 83.650 48.230 85.030 ;
        RECT 48.850 83.650 50.230 85.030 ;
        RECT 50.850 83.650 52.230 85.030 ;
        RECT 52.850 83.650 54.230 85.030 ;
        RECT 54.850 83.650 56.230 85.030 ;
        RECT 56.850 83.650 58.230 85.030 ;
        RECT 58.850 83.650 60.230 85.030 ;
        RECT 60.850 83.650 62.230 85.030 ;
        RECT 62.850 83.650 64.230 85.030 ;
        RECT 64.850 83.650 66.230 85.030 ;
        RECT 66.850 83.650 68.230 85.030 ;
        RECT 68.850 83.650 70.230 85.030 ;
        RECT 70.850 83.650 72.230 85.030 ;
        RECT 72.850 83.650 74.230 85.030 ;
        RECT 74.850 83.650 76.230 85.030 ;
        RECT 76.850 83.650 78.230 85.030 ;
        RECT 78.850 83.650 80.230 85.030 ;
        RECT 80.850 83.650 82.230 85.030 ;
        RECT 82.850 83.650 84.230 85.030 ;
        RECT 84.850 83.650 86.230 85.030 ;
        RECT 86.850 83.650 88.230 85.030 ;
        RECT 88.850 83.650 90.230 85.030 ;
        RECT 90.850 83.650 92.230 85.030 ;
        RECT 92.850 83.650 94.230 85.030 ;
        RECT 40.850 83.650 42.230 85.030 ;
        RECT 42.850 83.650 44.230 85.030 ;
        RECT 44.850 83.650 46.230 85.030 ;
        RECT 9.630 60.490 11.010 61.870 ;
        RECT 13.730 53.590 15.110 54.970 ;
        RECT 13.730 46.690 15.110 48.070 ;
        RECT -1.150 83.650 0.230 85.030 ;
        RECT 0.850 83.650 2.230 85.030 ;
        RECT 2.850 83.650 4.230 85.030 ;
        RECT 4.850 83.650 6.230 85.030 ;
        RECT 6.850 83.650 8.230 85.030 ;
        RECT 8.850 83.650 10.230 85.030 ;
        RECT 10.850 83.650 12.230 85.030 ;
        RECT 12.850 83.650 14.230 85.030 ;
        RECT 14.850 83.650 16.230 85.030 ;
        RECT 16.850 83.650 18.230 85.030 ;
        RECT 18.850 83.650 20.230 85.030 ;
        RECT 20.850 83.650 22.230 85.030 ;
        RECT 22.850 83.650 24.230 85.030 ;
        RECT 24.850 83.650 26.230 85.030 ;
        RECT 26.850 83.650 28.230 85.030 ;
        RECT 28.850 83.650 30.230 85.030 ;
        RECT 30.850 83.650 32.230 85.030 ;
        RECT 32.850 83.650 34.230 85.030 ;
        RECT 34.850 83.650 36.230 85.030 ;
        RECT 36.850 83.650 38.230 85.030 ;
        RECT 38.850 83.650 40.230 85.030 ;
        RECT 0.850 -0.240 2.230 1.140 ;
        RECT 2.850 -0.240 4.230 1.140 ;
        RECT 4.850 -0.240 6.230 1.140 ;
        RECT 6.850 -0.240 8.230 1.140 ;
        RECT 8.850 -0.240 10.230 1.140 ;
        RECT 10.850 -0.240 12.230 1.140 ;
        RECT 12.850 -0.240 14.230 1.140 ;
        RECT 14.850 -0.240 16.230 1.140 ;
        RECT 16.850 -0.240 18.230 1.140 ;
        RECT 18.850 -0.240 20.230 1.140 ;
        RECT 20.850 -0.240 22.230 1.140 ;
        RECT 22.850 -0.240 24.230 1.140 ;
        RECT 24.850 -0.240 26.230 1.140 ;
        RECT 26.850 -0.240 28.230 1.140 ;
        RECT 28.850 -0.240 30.230 1.140 ;
        RECT 30.850 -0.240 32.230 1.140 ;
        RECT 32.850 -0.240 34.230 1.140 ;
        RECT 34.850 -0.240 36.230 1.140 ;
        RECT 36.850 -0.240 38.230 1.140 ;
        RECT 38.850 -0.240 40.230 1.140 ;
        RECT 40.850 -0.240 42.230 1.140 ;
        RECT 42.850 -0.240 44.230 1.140 ;
        RECT 44.850 -0.240 46.230 1.140 ;
        RECT 37.560 2.450 38.920 6.040 ;
        RECT 42.940 2.450 44.300 6.040 ;
        RECT -1.150 -0.240 0.230 1.140 ;
        RECT 13.730 32.890 15.110 34.270 ;
        RECT 13.730 39.790 15.110 41.170 ;
        RECT 64.850 -0.240 66.230 1.140 ;
        RECT 66.850 -0.240 68.230 1.140 ;
        RECT 68.850 -0.240 70.230 1.140 ;
        RECT 70.850 -0.240 72.230 1.140 ;
        RECT 72.850 -0.240 74.230 1.140 ;
        RECT 74.850 -0.240 76.230 1.140 ;
        RECT 76.850 -0.240 78.230 1.140 ;
        RECT 78.850 -0.240 80.230 1.140 ;
        RECT 80.850 -0.240 82.230 1.140 ;
        RECT 82.850 -0.240 84.230 1.140 ;
        RECT 84.850 -0.240 86.230 1.140 ;
        RECT 86.850 -0.240 88.230 1.140 ;
        RECT 88.850 -0.240 90.230 1.140 ;
        RECT 90.850 -0.240 92.230 1.140 ;
        RECT 92.850 -0.240 94.230 1.140 ;
        RECT 46.850 -0.240 48.230 1.140 ;
        RECT 48.850 -0.240 50.230 1.140 ;
        RECT 62.300 3.700 63.660 8.540 ;
        RECT 50.850 -0.240 52.230 1.140 ;
        RECT 52.850 -0.240 54.230 1.140 ;
        RECT 70.210 37.390 71.590 38.770 ;
        RECT 54.850 -0.240 56.230 1.140 ;
        RECT 56.850 -0.240 58.230 1.140 ;
        RECT 58.850 -0.240 60.230 1.140 ;
        RECT 60.850 -0.240 62.230 1.140 ;
        RECT 62.850 -0.240 64.230 1.140 ;
      LAYER Metal3 ;
        RECT 68.815 12.220 69.215 12.620 ;
        RECT 74.015 12.220 74.415 12.800 ;
        RECT 80.115 12.220 80.515 12.800 ;
        RECT 75.350 12.880 75.750 13.280 ;
        RECT 81.450 12.880 81.850 13.280 ;
        RECT 69.830 12.880 70.230 13.360 ;
        RECT 72.830 12.880 73.230 13.360 ;
        RECT 76.250 12.880 79.550 13.360 ;
        RECT 88.410 12.880 88.810 13.360 ;
        RECT 33.700 13.050 35.580 14.370 ;
        RECT 33.485 14.370 35.580 14.430 ;
        RECT 29.540 14.370 30.920 15.030 ;
        RECT 31.640 14.370 33.020 15.030 ;
        RECT 29.540 15.030 33.020 15.750 ;
        RECT 33.485 14.430 35.530 15.750 ;
        RECT 30.885 15.750 32.970 16.410 ;
        RECT 13.730 32.890 15.110 32.940 ;
        RECT 29.590 15.750 30.870 32.940 ;
        RECT 31.690 16.410 32.970 32.940 ;
        RECT 33.750 15.750 35.530 32.940 ;
        RECT 13.730 32.940 35.530 34.220 ;
        RECT 13.730 34.220 15.110 34.270 ;
        RECT 13.730 39.790 15.110 39.840 ;
        RECT 29.590 34.220 30.870 39.840 ;
        RECT 31.690 34.220 32.970 39.840 ;
        RECT 33.750 34.220 35.030 39.840 ;
        RECT 13.730 39.840 35.030 41.120 ;
        RECT 13.730 41.120 15.110 41.170 ;
        RECT 13.730 46.690 15.110 46.740 ;
        RECT 29.590 41.120 30.870 46.740 ;
        RECT 31.690 41.120 32.970 46.740 ;
        RECT 13.730 46.740 32.970 48.020 ;
        RECT 13.730 48.020 15.110 48.070 ;
        RECT 13.730 53.590 15.110 53.640 ;
        RECT 29.590 48.020 30.870 53.640 ;
        RECT 13.730 53.640 30.870 54.920 ;
        RECT 13.730 54.920 15.110 54.970 ;
        RECT 45.665 13.710 47.045 15.090 ;
        RECT 9.630 60.490 11.010 60.540 ;
        RECT 45.715 15.090 46.995 60.540 ;
        RECT 9.630 60.540 46.995 61.820 ;
        RECT 9.630 61.820 11.010 61.870 ;
        RECT 87.515 12.220 87.915 12.620 ;
        RECT 87.565 12.620 87.865 69.980 ;
      LAYER Metal4 ;
        RECT 88.325 10.530 92.105 14.310 ;
        RECT 41.725 9.930 71.505 15.010 ;
        RECT 41.725 15.010 45.705 19.630 ;
        RECT 67.325 15.010 71.505 19.630 ;
        RECT 41.725 19.630 71.505 23.610 ;
        RECT 32.285 13.170 36.065 13.230 ;
        RECT 4.285 13.230 36.065 16.950 ;
        RECT 4.285 16.950 34.065 18.310 ;
        RECT 4.285 18.310 8.265 22.930 ;
        RECT 29.885 18.310 34.065 22.930 ;
        RECT 4.285 22.930 34.065 26.910 ;
      LAYER Metal5 ;
        RECT 43.715 13.020 69.315 14.460 ;
        RECT 33.575 14.460 69.315 15.660 ;
        RECT 43.715 15.660 69.315 21.620 ;
        RECT 6.275 10.420 90.815 11.620 ;
        RECT 89.615 11.620 90.815 13.020 ;
        RECT 6.275 11.620 7.475 16.320 ;
        RECT 6.275 16.320 31.875 24.920 ;
      LAYER Nwell ;
        RECT -1.260 71.430 92.160 84.790 ;
  END
END OPAM_SUMA
